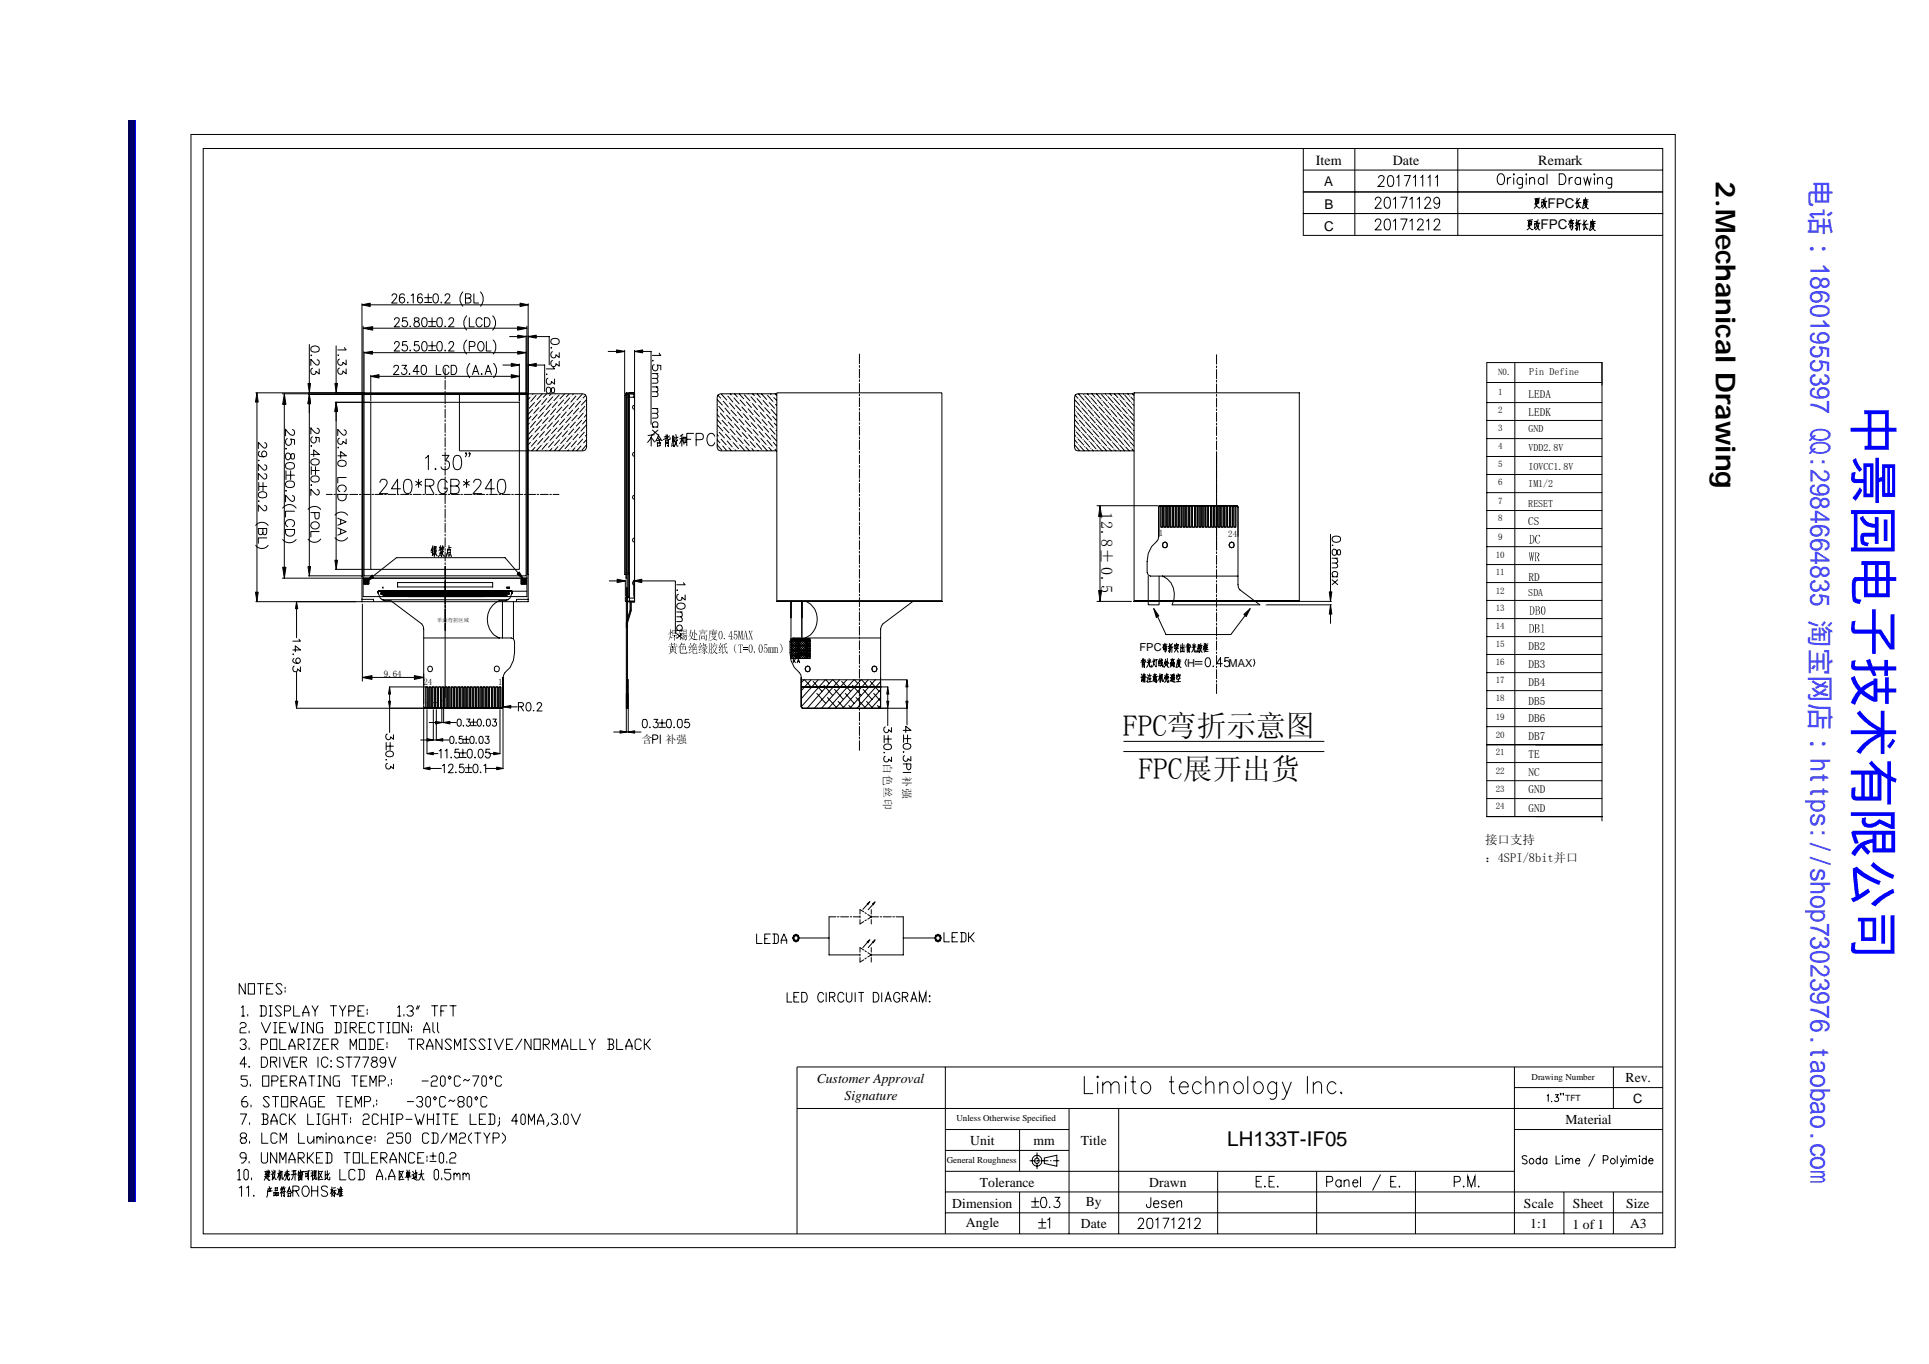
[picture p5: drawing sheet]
<svg xmlns="http://www.w3.org/2000/svg" width="297mm" height="210mm" viewBox="0 0 297 210" stroke-linecap="round" stroke-linejoin="round" font-family="sans-serif">
<defs><g id="words">
<text font-size="7.8" fill="#00f" x="285.7" y="62.3" transform="rotate(90 285.7 62.3)">中景园电子技术有限公司</text>
<g font-size="4.6">
<text x="172.9" y="113.3">FPC弯折示意图</text>
<text x="175.3" y="119.9">FPC展开出货</text>
</g>
<text font-size="4.2" x="264.2" y="27.9" transform="rotate(90 264.2 27.9)">2. Mechanical Drawing</text>
<text font-size="4.2" fill="#4040ff" x="278.8" y="27.7" transform="rotate(90 278.8 27.7)">电话：18601955397 QQ:2984664835 淘宝网店：https://shop73023976.taobao.com</text>
<text font-size="3.1" x="189" y="176.4">LH133T-IF05</text>
<text font-size="2.5" x="169.6" y="78.8" transform="rotate(90 169.6 78.8)">12.8±0.5</text>
<g font-size="2.2">
<text x="202.6" y="25.3">Item</text>
<text x="214.5" y="25.3">Date</text>
<text x="236.8" y="25.3">Remark</text>
</g>
<g font-size="2.1">
<text x="203.9" y="28.7">A</text>
<text x="203.9" y="35.6">C</text>
<text x="204" y="32.2">B</text>
<text x="237.2" y="35.3">FPC</text>
<text x="238.3" y="32">FPC</text>
<text x="125.8" y="166.6">Customer Approval</text>
<text x="250.3" y="166.6">Rev.</text>
<text x="130" y="169.4">Signature</text>
<text x="241.1" y="173.1">Material</text>
<text x="149.4" y="176.3">Unit</text>
<text x="159.1" y="176.3">mm</text>
<text x="166.4" y="176.3">Title</text>
<text x="146.6" y="185.9">Dimension</text>
<text x="150.9" y="182.7">Tolerance</text>
<text x="167.2" y="185.7">By</text>
<text x="177" y="182.7">Drawn</text>
<text x="234.7" y="185.9">Scale</text>
<text x="242.2" y="185.9">Sheet</text>
<text x="250.4" y="185.9">Size</text>
<text x="148.7" y="188.9">Angle</text>
<text x="166.4" y="189.1">Date</text>
<text x="235.6" y="189.1">1:1</text>
<text x="242.2" y="189.1">1 of 1</text>
<text x="251" y="189.1">A3</text>
</g>
<text font-size="2" x="251.5" y="169.8">C</text>
<g font-size="1.9">
<text x="228.7" y="130">接口支持</text>
<text x="228.7" y="132.7">：4SPI/8bit并口</text>
</g>
<g font-size="1.7">
<text x="235.4" y="64">LEDK</text>
<text x="235.4" y="61.2">LEDA</text>
<text x="235.3" y="80.8">CS</text>
<text x="235.4" y="89.4">RD</text>
<text x="175.5" y="100.3">FPC</text>
<text x="235.4" y="100.1">DB2</text>
<text x="182.8" y="102.6">H</text>
<text x="189.2" y="102.6">MAX</text>
<text x="235.4" y="102.8">DB3</text>
<text x="235.4" y="105.6">DB4</text>
<text x="235.4" y="108.6">DB5</text>
<text x="235.4" y="111.2">DB6</text>
<text x="235.4" y="113.9">DB7</text>
<text x="98.8" y="114.4">含</text>
<text x="102.5" y="114.4">补强</text>
<text x="136.1" y="117.4" transform="rotate(90 136.1 117.4)">白色丝印</text>
<text x="139.1" y="119.5" transform="rotate(90 139.1 119.5)">补强</text>
<text x="235.4" y="119.4">NC</text>
<text x="235.4" y="116.6">TE</text>
<text x="235.4" y="125">GND</text>
<text x="235.4" y="122.1">GND</text>
</g>
<g font-size="1.5">
<text x="235.5" y="57.8">Pin Define</text>
<text x="235.4" y="66.6">GND</text>
<text x="235.4" y="69.4">VDD2.8V</text>
<text x="235.3" y="74.9">IM1/2</text>
<text x="235.4" y="72.3">IOVCC1.8V</text>
<text x="235.3" y="78">RESET</text>
<text x="235.3" y="91.7">SDA</text>
</g>
<g font-size="1.4">
<text x="230.7" y="57.8">N0.</text>
<text x="230.7" y="60.9">1</text>
<text x="230.7" y="63.6">2</text>
<text x="230.7" y="66.4">3</text>
<text x="230.7" y="69.2">4</text>
<text x="230.7" y="71.9">5</text>
<text x="230.7" y="74.7">6</text>
<text x="230.7" y="77.5">7</text>
<text x="178.4" y="82.5">1</text>
<text x="189.1" y="82.6">24</text>
<text x="230.7" y="80.3">8</text>
<text x="230.7" y="83.1">9</text>
<text x="230.3" y="85.8">10</text>
<text x="230.3" y="88.6">11</text>
<text x="230.3" y="91.4">12</text>
<text x="230.3" y="94.1">13</text>
<text x="230.3" y="96.9">14</text>
<text x="230.3" y="99.7">15</text>
<text x="59.1" y="104.2">9.64</text>
<text x="65.2" y="105.4">24</text>
<text x="76.7" y="105.5">1</text>
<text x="230.3" y="102.4">16</text>
<text x="230.3" y="105.2">17</text>
<text x="230.3" y="108">18</text>
<text x="230.3" y="110.8">19</text>
<text x="230.3" y="113.5">20</text>
<text x="230.3" y="119.1">22</text>
<text x="230.3" y="116.3">21</text>
<text x="230.3" y="124.6">24</text>
<text x="230.3" y="121.9">23</text>
<text x="235.8" y="166.2">Drawing Number</text>
<text x="147.3" y="172.6">Unless Otherwise Specified</text>
<text x="145.8" y="179">General Roughness</text>
</g>
<text font-size="1.3" x="241" y="169.6">TFT</text>
<text font-size=".8" x="67.3" y="95.7">单面弯折区域</text>
</g></defs>
<path d="M20.9 18.6v166.5" fill="none" stroke="#00f" stroke-width=".25"/>
<path d="M19.9 18.6h.8v166.5h-.8z" fill="#00006b"/>
<path d="M19.8 18.6v166.5" fill="none" stroke="#005" stroke-width=".25"/>
<path d="M271 19.1h18.5v190.8h-18.5z" fill="#fff"/>
<g fill="none" stroke="#000" stroke-width=".15">
<path d="M29.4 20.7h228.6v171.4h-228.6zM31.3 22.9h224.7v167h-224.7zM200.7 26.2h55.3M200.7 29.5h55.3M200.7 22.9v13.3h55.3M200.7 32.9h55.3M208.6 22.9v13.3M211.8 30.8v-.3l.3-.1 .4 .1a.35 .35 0 0 1 .1 .5l-.9 1.1h1M211.8 34.1a.44 .44 0 0 1 .3-.4 .44 .44 0 0 1 .5 .3v.3l-.3 .5-.6 .6h1M212.3 27.4l.1-.2 .2-.2 .4 .1 .1 .3-.1 .4-.8 .9h1M213.4 30.5l.3-.1a.8 .8 0 0 1 .4 .9l-.2 .7-.3 .1a1.15 1.15 0 0 1-.2-1.6zM213.4 33.8l.3-.1a.79 .79 0 0 1 .4 1l-.2 .6-.3 .1a.77 .77 0 0 1-.5-1l.1-.4z"/>
<path d="M213.8 27.1l.4-.1a1.2 1.2 0 0 1 .2 1.6 .46 .46 0 0 1-.7-.2 1.67 1.67 0 0 1 .1-1.3zM214.6 30.7l.3-.3v1.7M214.6 34l.3-.3v1.7M215.1 27.3l.3-.3v1.7M215.7 30.4h1l-.7 1.7M215.7 33.7h1l-.7 1.7M216.2 27h1l-.7 1.7M217.1 30.7l.4-.3v1.7M217.1 34l.4-.3v1.7M217.6 27.3l.4-.3v1.7M218.2 30.7l.4-.3v1.7M218.3 34.1l.3-.4h.3l.2 .2a.65 .65 0 0 1-.1 .7l-.8 .8h1"/>
<path d="M218.7 27.3l.4-.3v1.7M219.4 30.8l.3-.4h.3l.3 .3-.2 .5-.7 .9h1M219.7 34l.3-.3v1.7M219.9 27.3l.3-.3v1.7M220.8 34.1l.3-.4h.3l.2 .2a.65 .65 0 0 1-.1 .7l-.7 .8h1M221 27.3l.3-.3v1.7M221.7 30.9a.5 .5 0 0 1-.5 .5 .51 .51 0 0 1-.4-.7 .51 .51 0 0 1 .8-.1 1.84 1.84 0 0 1-.1 1.4l-.4 .1-.3-.3M224.5 22.9v13.3M230.8 26.8a.57 .57 0 0 1 .6 0 .57 .57 0 0 1 .3 .6 .7 .7 0 0 1-.7 1 1.05 1.05 0 0 1-.2-1.6zM232.1 27.3v1.1M232.7 27.3a.49 .49 0 0 0-.6 .5M233.1 26.8h.1l-.1 .1z"/>
<path d="M233.1 27.3v1.1M234.4 27.3v1.6l-.2 .1-.4-.1M234.4 27.6a.45 .45 0 0 0-.5-.3 .45 .45 0 0 0-.3 .5v.3l.2 .2 .4 .1 .2-.2M235 26.8v.1zM235 27.3v1.1M235.3 34.8l.6 .6 .2-.1M235.4 34.1v.6M235.5 27.6l.4-.3 .3 .1 .1 .2v.8M235.5 27.3v1.1M235.6 33.9l-.1 1.1-.4 .4M235.8 34.4h-.4M235.9 34.1h-.5"/>
<path d="M235.9 34.6l-.5 .1M235.9 34l-.1 .6M236 33.8l-.8 .1M236.3 31.4l.7 .6h.2M236.3 34.4v.8l.3-.3M236.4 30.7v.7M236.6 34.1h-.3M236.6 34v.4M236.6 34.4l-.3 .1M236.7 30.5a1.31 1.31 0 0 1-.5 1.6M236.7 34.6l.3 .8h.2M236.8 33.8l-.2 1"/>
<path d="M236.9 31l-.4 .1M237 34.4a1.26 1.26 0 0 1-.6 1M237 30.8h-.6M237 31.2l-.6 .1M237 30.7l-.1 .5M237.1 30.5l-.8 .1M237.1 34.3l-.4 .1M237.4 31.1v.7M237.7 30.7l-.3 .1M237.7 30.7l-.1 .4M237.7 31.1h-.3M237.7 31.5l-.3 .4"/>
<path d="M237.7 27.6a.52 .52 0 0 0-.9 .1 .52 .52 0 0 0 .6 .7l.3-.2M237.7 27.3v1.1M237.8 31.2l.3 .8h.1M237.9 30.4l-.2 1M238.1 31a1.37 1.37 0 0 1-.6 1.1M238.2 31h-.4M238.2 26.8v1.6M240.1 26.8a.89 .89 0 0 1 1 .5 .89 .89 0 0 1-.3 1l-.7 .1zM241.6 27.3v1.1M241.8 34.1l-.3 .5M241.8 34.6v.4M241.9 34v.4"/>
<path d="M241.9 33.7l.1 .2M242 34v.4M242.1 34.1l.2 .3M242.2 35.1l-.2 .3-.1-.2M242.2 34.4l-.4 .1M242.2 27.3a.46 .46 0 0 0-.6 .5M242.2 34.4v.3l-.4 .1M242.2 34.9l-.4 .1M242.2 34.8v.4M242.3 33.9l-.7 .1M242.8 33.8v1.6l-.2-.3M242.8 30.5v1.5"/>
<path d="M242.9 34.5l-.3 .3M242.9 34.3l-.3 .1M243 31.2l.3 .7h.1M243 33.9l-.1 1.5M243.1 31.7l-.3 .3M243.2 30.5l-.4 .6M243.2 34.5v1M243.3 33.9l-.3 .2M243.4 27.6a.52 .52 0 0 0-.9 .1 .52 .52 0 0 0 .6 .7l.3-.2M243.4 27.3v1.1M243.4 31.2l-.9 .1M243.4 34.4l-.4 .1"/>
<path d="M243.9 27.3l.3 1.1 .2-1.1 .3 1.1 .3-1.1M243.9 30.7l-.3 1.4M243.9 33.9v1.4M244 31.6l.5 .5h.1M244 34.6l.4 .7 .1-.1M244.1 30.8v.6M244.1 30.4l.1 .3M244.1 35l-.2 .4M244.3 33.9l-.4 .5M244.3 30.8v.5M244.4 31.3h-.3M244.4 31.5h-.4"/>
<path d="M244.4 31.4l-.2 .5-.4 .2M244.5 30.8h-.6M244.5 31.1h-.6M244.5 34.5l-.9 .1M245 34l-.1 1.2-.2 .3M245.1 35l.6 .5M245.2 34.2v.6M245.2 33.8l.1 .3M245.4 26.8h.2l-.1 .1zM245.4 34.6l-.2 .1M245.4 34.1v.5M245.5 34.8l-.2 .4-.4 .3"/>
<path d="M245.5 34.8l-.4 .1M245.5 27.3v1.1M245.6 34.1l-.6 .1M245.6 34.4l-.6 .1M246 27.6l.4-.3 .3 .1 .1 1M246 27.3v1.1M248.2 27.3l-.1 1.6-.2 .1-.3-.1M248.2 27.6a.45 .45 0 0 0-.5-.3 .45 .45 0 0 0-.4 .5l.2 .5 .5 .1 .2-.2M47.4 59h.4l-.2 1.5zM47.6 53v6M47.9 53.5a.65 .65 0 0 1 .9-.3 .65 .65 0 0 1 .3 .8l-.2 .1a.62 .62 0 0 1-.7 .1 .62 .62 0 0 1-.3-.7zM48 54.7l-.1-.1v.2"/>
<path d="M48.1 56.7a.48 .48 0 0 0-.2 .7 .48 .48 0 0 0 .7 .1v-.4l.6 .5v-.8M48.8 55.4l.3 .1 .1 .4-.2 .2-.2 .1-.9-.9v1M51.6 59h.4l-.2 1.5zM51.8 53.2v5.8M52.1 54.7v-.1v.1M52.3 55.3a.47 .47 0 0 0-.3 .7 .47 .47 0 0 0 .7 .1l.1-.3 .5 .4v-.8M52.3 56.7a.49 .49 0 0 0-.3 .6 .49 .49 0 0 0 .7 .3l.1-.5 .5 .5v-.8M53.1 53.5l.2 .4h-1.3M55.7 46.8v13.5M55.7 46.9l1.3-.2v.5zM55.9 50.2v10.1M55.9 50.5l1.5-.2v.5z"/>
<path d="M56.1 54.3l1.2-.2v.4zM56.1 54.1v6.5M57 46.9h23.1M57.1 57.8v3.9M57.1 57.9l1.3-.2v.5zM57.3 54.3h22.4M57.4 50.5h22.3M58.4 57.9h20.3M60.4 45.6a.36 .36 0 0 1 .4-.4 .36 .36 0 0 1 .3 .4l-.8 1.1h.9M60.6 56.6a.36 .36 0 0 1 .4-.4 .36 .36 0 0 1 .4 .4l-.8 1.1h.8M60.8 52.9l.1-.2 .3-.1 .2 .1 .1 .3-.8 1h.8M60.8 49.2v-.2l.2-.1 .4 .1a1.02 1.02 0 0 1-.6 1.2l-.1 .1h.8"/>
<path d="M61.9 56.2h.7l-.4 .6a.44 .44 0 0 1 .4 .7 .44 .44 0 0 1-.8-.1M62.3 45.4a.38 .38 0 0 0-.4-.2 .38 .38 0 0 0-.3 .3 .88 .88 0 0 0 .3 1.2 .42 .42 0 0 0 .4-.4 .42 .42 0 0 0-.3-.5 .42 .42 0 0 0-.5 .4M62.6 52.6h-.6v.6a.46 .46 0 0 1 .7 0 .46 .46 0 0 1-.1 .7 .46 .46 0 0 1-.7-.1M62.6 48.9h-.6v.6l.2-.1h.3l.2 .2 .1 .3a.45 .45 0 0 1-.4 .4 .45 .45 0 0 1-.5-.3M62.8 46.5v.2l.1-.1M63.1 57.5v.2v-.1M63.2 53.9l-.1 .1h.1M63.2 50.2h-.1h.1M63.3 45.5l.3-.3v1.5M63.8 49v.2a.54 .54 0 0 0 .6 .4l.2 .2v.3l-.2 .2h-.4a.46 .46 0 0 1-.2-.6 .46 .46 0 0 1 .5-.3 .29 .29 0 0 0 .2-.4zM64.5 52.6h-.6l-.1 .6a.45 .45 0 0 1 .7 0 .45 .45 0 0 1-.1 .7 .45 .45 0 0 1-.7-.1M64.5 57.2h-.9l.6-1v1.5"/>
<path d="M65 56.3a.43 .43 0 0 1 .6 .2 .76 .76 0 0 1-.4 1.2 1.02 1.02 0 0 1-.2-1.4zM65 45.4l-.1-.1a.41 .41 0 0 0-.5 .2 .88 .88 0 0 0 .3 1.2 .41 .41 0 0 0 .4-.4 .41 .41 0 0 0-.4-.5 .41 .41 0 0 0-.4 .4M65.1 52.7l.3-.1a.95 .95 0 0 1 0 1.4h-.1a.8 .8 0 0 1-.3-1.1zM65.1 49a.39 .39 0 0 1 .6 .1 1.02 1.02 0 0 1-.3 1.2h-.1a.92 .92 0 0 1-.2-1.3zM65.4 45.8h1.1M65.4 46.6h1.1M65.9 45.2v1.2M66 53.2h1.1M66 54h1.1M66 49.5h1.1M66 50.2h1.1M66.5 48.9v1.2"/>
<path d="M66.5 52.6v1.2M66.9 45.3a.4 .4 0 0 1 .5 .2 .77 .77 0 0 1-.4 1.2 .97 .97 0 0 1-.1-1.4zM67.2 56.2v1.5h.7M67.4 52.7l.4-.1a.86 .86 0 0 1 .3 1.2 .4 .4 0 0 1-.7 .2 1.21 1.21 0 0 1 0-1.3zM67.4 49a.42 .42 0 0 1 .7 .1v.4a.59 .59 0 0 1-.5 .8 .92 .92 0 0 1-.2-1.3zM68 46.5v.2v-.1M68.5 45.6a.36 .36 0 0 1 .4-.4 .36 .36 0 0 1 .4 .4l-.8 1.1h.8M68.5 53.9v.1h.1M68.5 50.2h.1M68.5 56.7v1.1M68.5 58v.3M68.5 58.6v1.3"/>
<path d="M69.1 56.6a.47 .47 0 0 0-.5-.4 .47 .47 0 0 0-.4 .6 .71 .71 0 0 0 .6 .9l.3-.4M69.1 52.9l.1-.2a.4 .4 0 0 1 .6 0 .4 .4 0 0 1-.1 .6l-.6 .7h.8M69.1 49.2l.3-.3h.2l.3 .2-.2 .6-.6 .6h.8M69.5 56.2h.4a.79 .79 0 0 1 .4 .7 .79 .79 0 0 1-.4 .8h-.4zM71.3 44.9a1.56 1.56 0 0 0 0 2.2M71.7 45.9a.57 .57 0 0 0 .8-.4l-.3-.3h-.5v1.5h.5a.39 .39 0 0 0 .3-.4 .39 .39 0 0 0-.3-.4M71.9 52.3a1.51 1.51 0 0 0 0 2.2M71.9 48.6a1.56 1.56 0 0 0 0 2.2M72.3 53.3h.6l.2-.1v-.3l-.1-.2-.7-.1v1.4M72.3 48.9v1.4h.7M72.3 55.9a1.62 1.62 0 0 0 0 2.2M72.8 57.7l.4-1.5 .5 1.5"/>
<path d="M72.9 57.2h.6M73 45.2v1.5h.7M73.7 52.8l.2-.2a.78 .78 0 0 1 .7 .6 .78 .78 0 0 1-.3 .8 .64 .64 0 0 1-.7-.3 .64 .64 0 0 1 0-.7zM74 44.9a1.62 1.62 0 0 1 0 2.2M74.2 57.5v.2v-.1M74.2 49.2a.48 .48 0 0 0-.5-.3 .48 .48 0 0 0-.4 .5v.4a.52 .52 0 0 0 .8 .4l.1-.2M74.6 48.9h.4a.72 .72 0 0 1 .4 .9 .72 .72 0 0 1-.8 .5zM74.7 57.7l.5-1.5 .5 1.5M74.9 52.6v1.4h.7M74.9 57.2h.6M75.9 48.6a1.56 1.56 0 0 1 0 2.2M75.9 52.3a1.57 1.57 0 0 1 0 2.2"/>
<path d="M76 55.9a1.56 1.56 0 0 1 0 2.2M77.4 56.2h1.3M78.5 51.8h1.2M78.7 57.7l1.3 .2-1.3 .3zM78.7 55.9l1.3 .3-1.3 .2zM79.7 50.3l1.4 .2-1.4 .3zM79.7 54.1l1.3 .2-1.3 .2zM79.7 51.6l1.3 .2-1.3 .2zM80 56v5.7M80.1 46.7l1.2 .2-1.2 .3zM81 51.7v8.9M81.1 50.2v10.1"/>
<path d="M81.3 46.8v13.5M81.3 56.2l1.3-.3v.5zM81.3 51.8l1.3-.2v.4zM82.6 56.2h1.3v4.1M82.6 51.8h2v4.4M84.2 59.7h.1a.34 .34 0 0 1 .5 .1l.2 .6 .2 .1a.44 .44 0 0 0 .2-.5 .44 .44 0 0 0-.3-.3h-.1l-.2 .6-.3 .3-.2-.1-.2-.2zM84.3 57.6h-.1v.1M84.4 58.3a.49 .49 0 0 0-.2 .6 .49 .49 0 0 0 .6 .2l.1-.4 .5 .4v-.7M84.9 52.3a.77 .77 0 0 1 1.2 .2v.2a.73 .73 0 0 1-1.3 0zM84.9 53.6v-.1v.1M85.1 54.1a.46 .46 0 0 0-.2 .8 .46 .46 0 0 0 .7-.1v-.2l.5 .4v-.7M85.1 55.5a.46 .46 0 0 0-.2 .7 .46 .46 0 0 0 .7 0v-.2l.5 .4v-.8"/>
<path d="M85.1 56.5l.3 .3h-1.3M93.6 54.1h1.3M94.9 53.9l1.3 .2-1.3 .2zM96.2 53.9v6.8M97.7 53.9v6.4M97.7 54.1l1.3-.2v.4zM99 54.1h1.3v11.2M100.5 57.5h.8M100.5 59.6h.8M100.6 55.5h-.1v.1M100.7 56.1a.49 .49 0 0 0-.2 .8 .49 .49 0 0 0 .7 .1 .49 .49 0 0 0 0-.8l.6 .1v.6M101.1 57.5a.5 .5 0 0 1 .1 .7l-.7 .1"/>
<path d="M101.1 58.3a.52 .52 0 0 1 .1 .6l-.7 .1M101.1 59.6a.43 .43 0 0 1 0 .7h-.6M101.5 54.4l.3 .3h-1.3M132.3 54.5v1.5M132.3 56.3v.3M132.3 56.8v1.4M132.3 58.5v.2M132.3 59v1.4M187.3 54.6v1.4M187.3 56.3v.3M187.3 56.9v1.4M187.3 58.5v.3"/>
<path d="M187.3 59.1v1.4M228.9 58.9h17.8M233.3 55.8v69.9M39.4 60.5h41.9v32.1h-25.6M39.6 60.5h.1M39.6 61.9v29.3M39.6 60.5l.2 1.4h-.5zM39.8 75.9a.65 .65 0 0 1 .9-.2 .65 .65 0 0 1 .3 .8l-.5 .1a.59 .59 0 0 1-.7-.3zM39.8 74.3v1.2M39.9 70.9l-.1-.1v.2M39.9 77.2l-.1-.1v.1M40 69.5a.43 .43 0 0 0 0 .8 1.02 1.02 0 0 0 1-.2l.1-.3a.39 .39 0 0 0-.6-.3 .45 .45 0 0 0-.2 .5 .45 .45 0 0 0 .3 .3"/>
<path d="M40 74.9h1.1M40.5 74.3v1.2M40.8 68.2a.42 .42 0 0 1 .3 .4 .42 .42 0 0 1-.4 .4l-.9-.9v.9M40.8 71.6l.3 .2v.3l-.3 .3-.2-.1-.8-.8v.9M40.8 72.9l.1 .1 .2 .2-.1 .4-.2 .1h-.2l-.8-.8v.9M40.8 77.8l.3 .3v.3l-.3 .2h-.2l-.8-.9v1M43.5 60.6h12.1M43.5 78.2a1.27 1.27 0 0 1 2.1 0M43.8 62.3v25M43.8 60.6l.2 1.7h-.5zM44 71.4a.84 .84 0 0 1 1.3 .2v.2a.77 .77 0 0 1-.6 .4 .77 .77 0 0 1-.7-.4zM44 74.3a.84 .84 0 0 1 1.3 .2v.3a1.01 1.01 0 0 1-1.3 0z"/>
<path d="M44 72.5v1.3M44.1 69.8l.3-.1a1.15 1.15 0 0 1 .5 .9l.3 .1a.53 .53 0 0 0 0-.9l-.3 .1-.1 .4a.4 .4 0 0 1-.4 .5 .4 .4 0 0 1-.4-.4zM44.1 69.1l-.1-.1v.2M44.1 75.6l-.1-.1v.1M44.2 73.2h1.1M44.2 67.5a.53 .53 0 0 0-.2 .7 .53 .53 0 0 0 .7 .3l.2-.3-.1-.6 .5 .1v.7M44.8 72.5v1.3M45 66.1a.49 .49 0 0 1 .2 .9h-.3l-.4-.3-.5-.6v1M45 76.3l.2 .1a.54 .54 0 0 1 .1 .6l-.2 .2-.3-.1-.8-.9v1.1M45.3 78.7h-1.3v.9M47.4 78.4a1.24 1.24 0 0 1 2 0M47.5 60.7h8.4"/>
<path d="M47.6 60.5h.1M47.6 62.1v25.1M47.6 60.7l.2 1.4h-.4zM47.9 70h1.3l-.9-.7v1M47.9 78.9h1.3v.6l-.3 .4-.3-.1-.1-.9M47.9 70.8a.78 .78 0 0 1 1.3 .2v.2a.7 .7 0 0 1-.7 .4 .7 .7 0 0 1-.6-.4zM47.9 73.5a.77 .77 0 0 1 1.3 .2v.1a.68 .68 0 0 1-.7 .4 .68 .68 0 0 1-.6-.5zM47.9 71.8v1.2M48 68.7l-.1-.1v.1M48 74.7l-.1-.1v.1M48.1 72.4h1.1M48.1 67.2a.48 .48 0 0 0-.2 .7 .48 .48 0 0 0 .6 .2l.2-.5-.1-.3 .6 .1v.7"/>
<path d="M48.6 71.8v1.2M48.8 65.9l.3 .1v.5l-.1 .2h-.2l-.4-.2-.5-.7v1M48.8 75.4l.4 .2-.1 .5a.27 .27 0 0 1-.5 0l-.7-.8v1M50.3 76.1h.9M51.4 76.1h.3M51.6 79.3a1.21 1.21 0 0 1 1.9 0M51.6 61.9h5.3M51.8 60.5h.1M51.8 63.4v22.9M51.8 61.9l.2 1.5h-.4zM51.9 76.1h1.2M52 76.1h1.3a.69 .69 0 0 1-.4 1 .69 .69 0 0 1-.9-.5z"/>
<path d="M52 70.2h1.3l-.8-.7v1M52 79.8l1.3 .5-1.3 .6M52.1 71.1a.65 .65 0 0 1 .8-.3 .65 .65 0 0 1 .3 .8l-.1 .1a.62 .62 0 0 1-.8 .1 .62 .62 0 0 1-.2-.7zM52.1 68.9h-.1l.1 .1M52.3 67.5a.47 .47 0 0 0-.3 .6 .47 .47 0 0 0 .7 .2l.1-.4 .5 .4v-.7M52.3 75.7a.56 .56 0 0 1-.2-.7 .56 .56 0 0 1 .7-.3l.5 .3-.1 .5-.2 .2M52.5 80v.6M53 66.2l.3 .2v.3l-.2 .3-.5-.2-.6-.7v1M53.3 73.5h-1.3v.9M53.4 76.1h.2M53.9 76.1h1.2M55.3 76.1h.3"/>
<path d="M55.7 60.5v32.1M55.8 76.1h1.2M56.1 60.7h24.9v27.9h-24.9zM56.1 60.7v.1M57.1 61.9h22.9v25.8h-22.9zM57.1 61.9v.1M57.3 76.1h.2M57.7 76.1h1.3M58.5 74.3l.2-.4 .5-.1a.53 .53 0 0 1 .3 .8l-1.1 1.4h1.3M59.2 76.1h.3M59.7 76.1h1.2M61.2 76.1h.2"/>
<path d="M61.7 75.2h-1.4l.9-1.4v2.2M61.7 76.1h1.2M62.4 73.9a.64 .64 0 0 1 1 .3 2.16 2.16 0 0 1-.2 1.7 .62 .62 0 0 1-1-.3 2.03 2.03 0 0 1 .2-1.7zM63.1 76.1h.3M63.6 76.1h1.3M64 74.1l.9 .6M64.5 73.8v1.2M64.9 74.1l-.9 .6M65.1 76.1h.3M65.5 70.5l.5-.4v2.2M65.5 74.8a1.34 1.34 0 0 0 1.3-.3v-.3l-.2-.3-.3-.1h-.8v2.2M65.6 76.1h1.2"/>
<path d="M66.2 74.8l.6 1.2M67.1 72.1l-.1 .1 .1 .1v-.1M67.1 76.1h.2M67.6 76.1h1.2M68.1 70.1h1l-.5 .9a.69 .69 0 0 1 .6 .7 .69 .69 0 0 1-.8 .6l-.3-.1-.2-.3M68.5 60.2v.3M68.5 60.8v1.3M68.5 62.4v.3M68.5 63v1.3M68.5 64.6v.3M68.5 65.2v1.4M68.5 66.8v.3"/>
<path d="M68.5 67.4v1.4M68.5 69v.3M68.5 69.6v1.4M68.5 71.2v.3M68.5 71.8v1.4M68.5 73.4v.3M68.5 74v1.4M68.5 75.6v.3M68.5 76.2v1.3M68.5 77.8v.3M68.5 78.4v1.4M68.9 74.3a.7 .7 0 0 0-.8-.5 .7 .7 0 0 0-.6 .6 1.3 1.3 0 0 0 .5 1.6 .71 .71 0 0 0 .9-.9h-.5"/>
<path d="M69 76.1h.3M69.4 74.8a1.29 1.29 0 0 0 1.3-.3v-.3l-.2-.3-.3-.1h-.8v2.2h.8a.6 .6 0 0 0 .5-.6 .6 .6 0 0 0-.5-.6M69.5 76.1h1.2M70 70.2a.62 .62 0 0 1 1 .3 2.06 2.06 0 0 1-.2 1.7 .62 .62 0 0 1-.9-.3 2.08 2.08 0 0 1 .1-1.7zM70.7 60.6v8.8h19.1l.4-.1 .1-.4v-7.7l-.1-.4-.4-.2h-33.9v31.2h25.2v-31.2M71 76.1h.2M71.4 74.1l.9 .6M71.5 76.1h1.2M71.8 69.8l-.1 .1v-.1v-.1a.42 .42 0 0 1 0 .6M71.8 73.8v1.2M72.3 74.1l-.9 .6M72.4 69.8l-.1 .1v-.2a.44 .44 0 0 1-.1 .6"/>
<path d="M72.9 74.3l.2-.4 .6-.1a.53 .53 0 0 1 .3 .8l-1.2 1.4h1.4M72.9 76.1h.3M73.4 76.1h1.2M74.9 76.1h.2M75.4 76.1h1.2M76.1 75.2h-1.4l.9-1.4v2.2M76.8 76.1h.3M76.9 73.9a.59 .59 0 0 1 .9 .3 2.14 2.14 0 0 1-.2 1.7 .62 .62 0 0 1-.9-.3 2.03 2.03 0 0 1 .2-1.7zM77.3 76.1h1.3M78.8 76.1h.2M79.3 76.1h1.2M80 61.9v.1"/>
<path d="M80.8 76.1h.2M81 60.7v.1M81.2 67.1h.1M81.2 76.1h1.3M81.3 63.1h.1M81.3 66.2l-.1 .1M81.4 62.2l-.2 .2M81.4 60.6l-.2 .3M81.5 66h.1M81.5 69.1l-.3 .3M81.5 62h.1M81.5 65.1l-.3 .4"/>
<path d="M81.6 61.2l-.4 .4M81.6 68.9h.1M81.7 64.9v.1M81.7 68.1l-.5 .6M81.8 60.9v.1M81.8 64.1l-.6 .7M81.9 67.8v.1M82 63.9h.1M82 67l-.8 .9M82 63l-.8 .9M82.1 60.6l-.1 .2M82.2 66.8h.1"/>
<path d="M82.2 62.8h.1M82.2 65.9l-.8 1M82.3 61.9l-.8 1M82.4 65.7h.1M82.4 68.8l-.5 .6M82.5 61.7h.1M82.5 64.8l-.9 1M82.6 60.8l-.9 1M82.6 68.6v.1M82.7 64.7h.1M82.7 67.7l-.9 1M82.7 76.1h.3"/>
<path d="M82.7 60.7h.1M82.7 63.8l-.8 .9M82.8 67.6h.1M82.9 63.6h.1M82.9 66.7l-.9 1M83 62.7l-.8 1M83.1 66.5h.1M83.2 62.5h.1M83.2 65.6l-.9 1M83.2 76.1h1.2M83.3 61.6l-.9 1M83.3 69.4h.1"/>
<path d="M83.4 65.4v.1M83.4 68.5l-.8 .9M83.4 61.4v.1M83.4 64.6l-.8 .9M83.5 60.6l-.8 .9M83.5 68.3v.1M83.6 64.3v.1M83.6 67.5l-.9 1M83.7 63.5l-.9 1M83.8 67.3h.1M83.9 63.3h.1M83.9 66.4l-.9 1"/>
<path d="M84 62.4l-.9 1M84.1 66.2h.1M84.1 69.3l-.1 .1M84.1 62.2v.1M84.1 65.3l-.8 1M84.2 60.6l-.6 .6M84.2 61.3l-.8 1M84.2 69.1v.1M84.3 65.1v.1M84.3 68.2l-.9 1M84.4 61.2h.1M84.4 64.3l-.9 .9"/>
<path d="M84.5 68.1h.1M84.6 64.1h.1M84.6 67.2l-.9 .9M84.7 63.2l-.9 1M84.7 76.1h.2M84.8 67h.1M84.8 63h.1M84.8 66.1l-.8 1M84.9 60.6l-.3 .3M84.9 62.1l-.8 1M85 65.9h.1M85 69l-.3 .4"/>
<path d="M85.1 61.9v.1M85.1 65l-.9 1M85.2 61l-.9 1M85.2 68.8v.1M85.2 76.1h.9M85.3 64.8v.1M85.3 67.9l-.9 1M85.4 60.8v.1M85.4 63.9l-.9 1M85.5 67.7v.1M85.5 63.8h.1M85.5 66.9l-.8 .9"/>
<path d="M85.6 60.6l-.1 .1M85.6 62.9l-.8 1M85.7 66.7h.1M85.8 62.7h.1M85.8 65.8l-.9 1M85.9 61.8l-.9 1M85.9 65.6h.1M85.9 68.7l-.5 .7M86 61.6h.1M86 64.7l-.8 1M86.1 60.8l-.8 .9M86.1 68.5v.1"/>
<path d="M86.2 64.6h.1M86.2 67.7l-.8 .9M86.3 63.7l-.8 1M86.4 67.5h.1M86.5 63.5h.1M86.5 66.6l-.9 1M86.6 62.6l-.9 1M86.6 66.4h.1M86.7 62.4h.1M86.7 65.5l-.8 1M86.8 61.5l-.9 1M86.8 69.3h.1"/>
<path d="M86.9 65.3v.1M86.9 68.5l-.9 .9M87 60.6l-.8 .8M87 61.3v.1M87 64.5l-.9 .9M87.1 68.2v.1M87.2 64.3h.1M87.2 67.4l-.9 .9M87.2 63.4l-.8 .9M87.3 67.2h.1M87.4 63.2h.1M87.4 66.3l-.8 1"/>
<path d="M87.5 62.3l-.9 1M87.6 66.1h.1M87.6 69.2l-.2 .2M87.7 60.6l-.5 .6M87.7 62.1h.1M87.7 65.2l-.9 1M87.8 61.2l-.9 1M87.8 69h.1M87.9 65v.1M87.9 68.1l-.9 1M87.9 61v.1M87.9 64.2l-.8 .9"/>
<path d="M88 67.9v.1M88.1 63.9v.1M88.1 67.1l-.9 1M88.2 63.1l-.9 1M88.3 66.9h.1M88.3 60.6l-.2 .2M88.4 62.9h.1M88.4 66l-.9 1M88.5 62l-.9 1M88.6 65.8h.1M88.6 68.9l-.5 .5M88.6 61.8v.1"/>
<path d="M88.6 64.9l-.8 1M88.7 60.9l-.8 1M88.7 68.7v.1M88.8 64.7v.1M88.8 67.8l-.9 1M88.9 60.8h.1M88.9 63.9l-.9 .9M89 67.7h.1M89.1 63.7h.1M89.1 66.8l-.9 .9M89.2 62.8l-.9 1M89.2 66.6h.1"/>
<path d="M89.3 62.6h.1M89.3 65.7l-.8 1M89.4 61.7l-.8 1M89.5 65.5h.1M89.5 68.6l-.7 .8M89.6 61.5v.1M89.6 64.7l-.9 .9M89.7 60.7l-.9 .9M89.7 68.5h.1M89.8 64.5h.1M89.8 67.6l-.9 .9M89.8 63.6l-.8 1"/>
<path d="M89.9 67.4h.1M90 63.4h.1M90 66.5l-.8 1M90.1 62.5l-.9 1M90.2 66.3h.1M90.2 60.8l-.4 .5M90.3 62.3v.1M90.3 65.4l-.9 1M90.3 61.5l-.8 .9M90.3 63l-.1 .2M90.3 63.8l-.4 .5M90.3 64.6l-.6 .7"/>
<path d="M90.3 66.9l-.2 .3M90.3 67.7l-.5 .5M90.3 68.5l-.7 .8M96.4 60.8h-.2v27.6h.2M96.5 60.6v31.2h.2v-31.2M96.7 60.8h.2M96.9 60.5v31.5h-.6v.6h1.4M97 60.5h.7M97.6 61.2v-.6h-1.2v28.4h.1M97.7 76.2l-.2 .1-.1 .2 .1 .3 .2 .1M97.7 69.6l-.2 .1-.1 .3 .1 .2 .2 .1M97.7 62.4l-.2 .1-.1 .2 .1 .2 .2 .1"/>
<path d="M97.7 60.5h-1.3v.1M97.7 60.5v32.1h-1.3v-.1h1.3M97.7 61.2h-1.3v27h.5v4.3M100.3 67.4v1.3M100.4 67l-.2 .5-.5 .6M100.4 67.5l.4 .6M100.5 62.9h.8M100.5 65.7h.8M100.5 66.2l.8 .8M100.7 65.7a.44 .44 0 0 1-.1-.6 .44 .44 0 0 1 .6 0 .44 .44 0 0 1 0 .6M100.8 66.9l-1 .1M101.1 60.3a.43 .43 0 0 1 0 .7h-.6"/>
<path d="M101.1 62.9a.5 .5 0 0 1 .1 .7h-.7M101.1 63.6a.52 .52 0 0 1 .1 .7l-.7 .1M101.2 68.1v.6M101.3 66.2l-.8 .8M101.4 67.4l.1 .3M101.4 67.1l.5 .7h.1M101.4 66.9l-.4 1M101.6 67.7l-.1 .5M101.6 67.7l-.4 .1M101.7 68.6l-.5 .1M101.7 68.2h-.5M101.7 68.1l-.1 .5"/>
<path d="M102.5 67.8v1M102.6 66.9v.8M102.6 67.5l-.4 .2M102.6 67.2l-.3 .1M102.8 66.9v.8l.4-.1v-.2M102.8 68.1h-.3M102.8 68.3h-.3M102.9 67.8v.9l-.1-.1M102.9 67.8l-.4 .1M103.1 67.1l-.3 .3M103.6 67.1v.8M103.6 67.9l-.2 .8"/>
<path d="M103.6 68.6l.1 .1M103.7 67.9h-.1M103.7 67.6h-.1M103.7 67.1v1.6M103.7 67.2h-.1M104 67.9l.3 .8h.1M104 67.6l-.2 .3M104.1 66.9v.3M104.2 67.8l-.4 1M104.2 67.5l.1 .3M104.4 67.3l-.6 .1M105 67.7l.2 .2"/>
<path d="M105 67.6l-.3 .7M105 67v1.7M105.2 66.8l-.5 .4M105.2 67.4l-.5 .2M105.3 67.2v1.2M105.6 67.4h-.3M105.6 67.3v.8M105.6 68.1l-.3 .1M105.8 67.6h.6M106.8 66.7h-1v1.9M107.2 67.7a1 1 0 0 0 1.1-.3v-.3l-.2-.3-.2-.1h-.7v1.9M110.1 67.2a.59 .59 0 0 0-.8-.5 1.18 1.18 0 0 0 0 1.9 .58 .58 0 0 0 .8-.4"/>
<path d="M110.4 68.5l.8 .8M110.4 67.7l.5 .5M110.4 66.9l.2 .3M110.4 64.6l.7 .7M110.4 63.8l.4 .5M110.4 63l.2 .2M110.4 61.5l.9 .9M110.5 65.4l.8 1M110.5 62.3v.1M110.5 60.8l.5 .5M110.6 66.3h.1M110.6 62.5l.9 1"/>
<path d="M110.7 66.5l.9 1M110.7 63.4h.1M110.8 67.4h.1M110.9 63.6l.8 1M111 67.6l.9 .9M111 64.5h.1M111.1 68.5h.1M111.1 60.7l.8 .9M111.2 64.7l.8 .9M111.2 61.5v.1M111.3 68.6l.6 .8M111.3 65.5h.1"/>
<path d="M111.3 61.7l.9 1M111.4 65.7l.9 1M111.4 62.6h.1M111.5 66.6h.1M111.6 62.8l.8 1M111.7 66.8l.8 .9M111.7 63.7h.1M111.7 67.7h.1M111.9 63.9l.8 .9M111.9 60.8h.1M111.9 67.8l.9 1M111.9 64.7v.1"/>
<path d="M112 68.7v.1M112 60.9l.9 1M112.1 64.9l.9 1M112.1 61.8v.1M112.2 68.9l.4 .5M112.2 65.8h.1M112.3 62l.9 1M112.4 66l.8 1M112.4 62.9h.1M112.4 60.6l.2 .2M112.4 66.9h.1M112.5 63.1l.9 1"/>
<path d="M112.6 67.1l.9 1M112.6 63.9v.1M112.7 67.9v.1M112.8 64.2l.9 .9M112.8 61v.1M112.9 68.1l.9 1M112.9 65v.1M113 69h.1M113 61.2l.9 1M113.1 65.2l.8 1M113.1 62.1h.1M113.1 60.6l.5 .6"/>
<path d="M113.2 69.2l.1 .2M113.2 66.1h.1M113.2 62.3l.9 1M113.3 66.3l.9 1M113.3 63.2h.1M113.4 67.2h.1M113.5 63.4l.9 .9M113.6 67.4l.9 .9M113.6 64.3h.1M113.7 68.2v.1M113.8 64.5l.8 .9M113.8 61.3v.1"/>
<path d="M113.8 60.6l.8 .8M113.9 68.5l.8 .9M113.9 65.3v.1M113.9 69.3h.1M113.9 61.5l.9 1M114 65.5l.9 1M114 62.4h.1M114.1 66.4h.1M114.2 62.6l.8 1M114.3 66.6l.9 1M114.3 63.5h.1M114.4 67.5h.1"/>
<path d="M114.5 63.7l.8 1M114.6 67.7l.8 .9M114.6 64.6h.1M114.6 68.5v.1M114.6 60.8l.9 .9M114.7 64.7l.9 1M114.7 61.6h.1M114.8 68.7l.6 .7M114.8 65.6h.1M114.9 61.8l.8 1M115 65.8l.8 1M115 62.7h.1"/>
<path d="M115 66.7h.1M115.2 62.9l.8 1M115.2 60.6v.1M115.2 66.9l.9 .9M115.2 63.8h.1M115.3 67.7v.1M115.4 63.9l.9 1M115.4 60.8v.1M115.5 67.9l.8 1M115.5 64.8v.1M115.6 68.8v.1M115.6 61l.8 1"/>
<path d="M115.6 65l.9 1M115.6 61.9v.1M115.7 69l.4 .4M115.7 65.9h.1M115.8 62.1l.9 1M115.9 60.6l.3 .3M115.9 66.1l.9 1M115.9 63h.1M116 67h.1M116.1 63.2l.9 1M116.2 67.2l.8 .9M116.2 64.1h.1"/>
<path d="M116.3 68.1h.1M116.3 64.3l.9 .9M116.3 61.2h.1M116.4 68.2l.9 1M116.4 65.1v.1M116.5 69.1v.1M116.5 61.3l.9 1M116.6 60.6l.5 .6M116.6 65.3l.9 1M116.6 62.2v.1M116.7 69.3l.1 .1M116.7 66.2h.1"/>
<path d="M116.8 62.4l.9 1M116.9 66.4l.8 1M116.9 63.3h.1M117 67.3h.1M117 63.5l.9 1M117.1 67.5l.9 1M117.1 64.3v.1M117.2 68.3v.1M117.2 60.6l.9 .9M117.3 64.6l.9 .9M117.3 61.4v.1M117.4 68.5l.8 .9"/>
<path d="M117.4 65.4v.1M117.5 69.4h.1M117.5 61.6l.8 1M117.6 65.6l.8 1M117.6 62.5h.1M117.7 66.5h.1M117.7 62.7l.9 1M117.8 66.7l.9 1M117.8 63.6h.1M117.9 67.6h.1M118 63.8l.9 .9M118 60.7h.1"/>
<path d="M118.1 67.7l.8 1M118.1 64.7h.1M118.2 68.6v.1M118.2 60.8l.8 1M118.3 64.8l.8 1M118.3 61.7h.1M118.3 68.8l.6 .6M118.3 65.7h.1M118.4 61.9l.9 1M118.5 65.9l.9 1M118.5 62.8h.1M118.6 66.8h.1"/>
<path d="M118.6 60.6l.2 .2M118.7 63l.9 .9M118.8 67l.8 .9M118.8 63.9h.1M118.9 67.8v.1M118.9 64.1l.7 .7M118.9 60.9v.1M119 68.1l.6 .6M119 64.9v.1M119.1 68.9h.1M119.1 61.2l.5 .4M119.2 65.1l.4 .4"/>
<path d="M119.2 62h.1M119.3 69.1l.3 .3M119.3 66h.1M119.3 60.6l.3 .3M119.4 62.2l.2 .2M119.5 66.2l.1 .1M119.5 63.1h.1M119.6 67.1h.1M119.6 60.6h-8.7l-.3 .2-.2 .4v7.7l.2 .4 .3 .1h8.7M119.6 60.5h25.4v32.1h-25.4zM132.3 60.7v.2M132.3 61.2v1.4"/>
<path d="M132.3 62.9v.2M132.3 63.4v1.4M132.3 65.1v.2M132.3 65.6v1.4M132.3 67.3v.3M132.3 67.8v1.4M132.3 69.5v.2M132.3 70v1.4M132.3 71.7v.2M132.3 72.2v1.4M132.3 73.9v.2M132.3 74.4v1.4"/>
<path d="M132.3 76.1v.2M132.3 76.6v1.4M132.3 78.3v.2M132.3 78.8v1.4M165.5 68.5l.7 .8M165.5 67.7l.4 .5M165.5 66.9l.2 .3M165.5 64.6l.6 .7M165.5 63.8l.3 .5M165.5 63l.1 .2M165.5 61.5l.8 .9M165.5 65.4l.8 1"/>
<path d="M165.5 62.3v.1M165.6 66.3h.1M165.6 60.8l.4 .5M165.7 62.5l.8 1M165.7 66.5l.9 1M165.7 63.4h.1M165.8 67.4h.1M165.9 63.6l.9 1M166 67.6l.9 .9M166 64.5h.1M166.1 68.5h.1M166.1 60.7l.8 .9"/>
<path d="M166.2 64.7l.8 .9M166.2 61.5v.1M166.3 68.6l.7 .8M166.3 65.5h.1M166.3 61.7l.9 1M166.4 65.7l.9 1M166.4 62.6h.1M166.5 66.6h.1M166.6 62.8l.9 1M166.7 66.8l.9 .9M166.7 63.7h.1M166.8 67.7h.1"/>
<path d="M166.9 63.9l.8 .9M166.9 60.8h.1M166.9 67.8l.9 1M166.9 64.7v.1M167 68.7v.1M167 60.9l.9 1M167.1 64.9l.9 1M167.1 61.8v.1M167.2 68.9l.5 .5M167.2 65.8h.1M167.3 62l.9 1M167.4 66l.9 1"/>
<path d="M167.4 62.9h.1M167.4 60.6l.2 .2M167.5 66.9h.1M167.6 63.1l.8 1M167.6 67.1l.9 1M167.6 63.9v.1M167.7 67.9v.1M167.8 64.2l.9 .9M167.8 61v.1M167.9 68.1l.9 1M167.9 65v.1M168 69h.1"/>
<path d="M168 61.2l.9 1M168.1 65.2l.9 1M168.1 62.1h.1M168.1 60.6l.5 .6M168.2 69.2l.1 .2M168.2 66.1h.1M168.3 62.3l.8 1M168.3 66.3l.9 1M168.3 63.2h.1M168.4 67.2h.1M168.5 63.4l.9 .9M168.6 67.4l.8 .9"/>
<path d="M168.6 64.3h.1M168.7 68.2v.1M168.8 64.5l.8 .9M168.8 61.3v.1M168.8 60.6l.8 .8M168.9 68.5l.8 .9M168.9 65.3v.1M168.9 77.9h9.5M169 69.3h.1M169 61.5l.8 1M169 62.4h.1M169 65.5l.9 1"/>
<path d="M169.1 66.4h.1M169.2 62.6l.9 1M169.3 66.6l.8 1M169.3 63.5h.1M169.4 67.5h.1M169.4 79.5v11.4M169.4 77.9l.2 1.6h-.4zM169.4 63.7l.9 1M169.6 67.7l.8 .9M169.6 64.6h.1M169.6 68.5v.1M169.6 60.8l.9 .9"/>
<path d="M169.7 64.7l.9 1M169.7 61.6h.1M169.8 65.6h.1M169.8 68.7l.6 .7M169.9 61.8l.8 1M170 65.8l.8 1M170 62.7h.1M170.1 66.7h.1M170.1 62.9l.9 1M170.2 60.6l.1 .1M170.3 66.9l.8 .9M170.3 63.8h.1"/>
<path d="M170.3 67.7v.1M170.4 63.9l.9 1M170.4 60.8v.1M170.5 67.9l.9 1M170.5 64.8v.1M170.6 68.8v.1M170.6 61l.8 1M170.7 65l.8 1M170.7 61.9v.1M170.7 69l.4 .4M170.7 65.9h.1M170.8 62.1l.9 1"/>
<path d="M170.9 60.6l.3 .3M170.9 66.1l.9 1M170.9 63h.1M171 67h.1M171.1 63.2l.9 1M171.2 67.2l.9 .9M171.2 64.1h.1M171.3 68.1h.1M171.4 64.3l.8 .9M171.4 61.2h.1M171.4 68.2l.9 1M171.4 65.1v.1"/>
<path d="M171.5 69.1v.1M171.5 61.3l.9 1M171.6 60.6l.5 .6M171.6 65.3l.9 1M171.6 62.2v.1M171.7 69.3l.1 .1M171.7 66.2h.1M171.8 62.4l.9 1M171.9 66.4l.8 1M171.9 63.3h.1M172 67.3h.1M172.1 63.5l.8 1"/>
<path d="M172.1 67.5l.9 1M172.1 64.3v.1M172.2 68.3v.1M172.3 60.6l.8 .9M172.3 64.6l.9 .9M172.3 61.4v.1M172.4 68.5l.8 .9M172.4 65.4v.1M172.5 69.4h.1M172.5 61.6l.9 1M172.6 65.6l.8 1M172.6 62.5h.1"/>
<path d="M172.7 66.5h.1M172.7 62.7l.9 1M172.9 66.7l.8 1M172.9 63.6h.1M172.9 67.6h.1M173 63.8l.9 .9M173 60.7h.1M173.1 67.7l.9 1M173.1 64.7h.1M173.2 68.6v.1M173.2 60.8l.8 1M173.3 64.8l.8 1"/>
<path d="M173.3 61.7h.1M173.4 68.8l.5 .6M173.4 65.7h.1M173.4 61.9l.9 1M173.5 65.9l.9 1M173.5 62.8h.1M173.6 66.8h.1M173.7 60.6l.1 .2M173.7 63l.9 .9M173.8 67l.8 .9M173.8 63.9h.1M173.9 67.8v.1"/>
<path d="M174 64.1l.6 .7M174 60.9v.1M174 68.1l.6 .6M174 64.9v.1M174.1 68.9h.1M174.1 61.2l.5 .4M174.2 65.1l.4 .4M174.2 62h.1M174.3 69.1l.3 .3M174.3 66h.1M174.4 60.6l.2 .3M174.4 62.2l.2 .2"/>
<path d="M174.5 66.2l.1 .1M174.5 63.1h.1M174.6 67.1h.1M174.6 60.6h-8.7l-.3 .2-.1 .4v7.7l.1 .4 .3 .1h8.7M178.8 77.9h.2v3.3h-.2zM178.8 77.9h.1M179.2 77.9h.3v3.3h-.3zM179.7 77.9h.3v3.3h-.3zM180.2 77.9h.3v3.3h-.3zM180.7 77.9h.3v3.3h-.3zM181.2 77.9h.3v3.3h-.3zM181.7 77.9h.3v3.3h-.3z"/>
<path d="M182.2 77.9h.3v3.3h-.3zM182.7 77.9h.3v3.3h-.3zM183.2 77.9h.2v3.3h-.2zM183.6 77.9h.3v3.3h-.3zM184.1 77.9h.3v3.3h-.3zM184.6 77.9h.3v3.3h-.3zM185.1 77.9h.3v3.3h-.3zM185.6 77.9h.3v3.3h-.3zM186.1 77.9h.3v3.3h-.3zM186.6 77.9h.3v3.3h-.3zM187.1 77.9h.3v3.3h-.3zM187.3 60.7v.3"/>
<path d="M187.3 61.3v1.4M187.3 62.9v.3M187.3 63.5v1.4M187.3 65.2v.2M187.3 65.7v1.4M187.3 67.4v.2M187.3 67.9v1.4M187.3 69.5v15.2M187.6 77.9h.2v3.3h-.2zM188 77.9h.3v3.3h-.3zM188.5 77.9h.3v3.3h-.3zM189 77.9h.3v3.3h-.3z"/>
<path d="M189.5 77.9h.3v3.3h-.3zM190 77.9h.3v3.3h-.3zM228.9 62h17.8M228.9 64.7h17.8M228.9 67.5h17.8M228.9 70.3h17.8M228.9 73h17.8M228.9 75.8h17.8M228.9 78.6h17.8M39.3 91.2h.5l-.2 1.4zM39.4 80.9a1.17 1.17 0 0 1 1.9 0M39.4 83.9a1.17 1.17 0 0 0 1.9 0"/>
<path d="M39.4 92.6h16.2M40.5 81.4v.8l.2 .1h.2l.2-.3v-.6h-1.3v.8a.33 .33 0 0 0 .6 0l.1-.2M41.1 82.8h-1.3v.8M43.5 89h12.1M43.5 83.1a1.34 1.34 0 0 0 2.1 0M43.5 87.3h.5l-.2 1.7zM43.8 89h.1M44 81.5h1.3a.74 .74 0 0 1-.4 1 .74 .74 0 0 1-.9-.5zM44.3 81.1a.64 .64 0 0 1-.1-1 .64 .64 0 0 1 1 0 .57 .57 0 0 1-.2 1M45.7 92.6h.1M45.7 93.7v4.5M45.7 92.6l.2 1.1h-.4z"/>
<path d="M46 98.4l.3 .3h-1.2M47.4 87.2h.4l-.2 1.4zM47.4 83a1.19 1.19 0 0 0 2 0M47.5 88.6h8.4M47.6 88.6v.1M47.9 80.6a.67 .67 0 0 1 .8-.2 .67 .67 0 0 1 .5 .6 .64 .64 0 0 1-.9 .4 .64 .64 0 0 1-.4-.8zM49.2 81.8h-1.3v.9M51.6 86.3h.4l-.2 1.4zM51.6 82.8a1.19 1.19 0 0 0 1.9 0M51.6 87.7h5.3M51.8 87.7h.1M52 81.3l1.3 .5-1.3 .6"/>
<path d="M52.5 81.5v.7M55.7 92.3h1.8v.3M55.8 92.6h.1M55.8 93v11.9M55.9 89h25.2M56 89h.8v.9h-.8zM56 89h.2l-.2 .9zM56 89v.9zM56.1 88.6v.1M56.2 89h.4l-.4 .3zM56.2 89.3l.4-.3v.3zM56.2 89.6h.4l-.4 .3z"/>
<path d="M56.2 89.9l.4-.3v.3zM56.2 89v.9h-.2zM56.3 89.5l.1-.2v.2M56.3 89.5h.1M56.6 89h.2l-.2 .9zM56.6 89.4l-.1 .2M56.6 89.4h-.1l.1 .1M56.8 89v.9zM56.8 89v.9h-.2zM57.1 87.7h.1M57.3 88.5l.2 .4-1.1 .6zM58.7 91.2l.3 .1v.1l-.3 .1-.1-.1z"/>
<path d="M58.8 92.3h19.5M58.9 90.4h.1v.2M59 91h.1v.7h-.1zM59.1 91h.1v.7h-.1zM59.3 91h.1v.7h-.1zM59.4 91h.1v.7h-.1zM59.5 91h.2v.7h-.2zM59.7 91h.1v.7h-.1zM59.8 91h.2v.7h-.2zM60 91h.1v.7h-.1zM60.1 91h.1v.7h-.1zM60.3 91h.1v.7h-.1z"/>
<path d="M60.4 91h.1v.7h-.1zM60.6 91v.7zM60.7 91h.1v.7h-.1zM60.8 91h.1v.7h-.1zM61 91h.1v.7h-.1zM61.1 91h.1v.7h-.1zM61.2 89.7h14.7v.7h-14.7zM61.3 91h.1v.7h-.1zM61.4 91h.1v.7h-.1zM61.6 91h.1v.7h-.1zM61.7 91h.1v.7h-.1zM61.8 91h.1v.7h-.1z"/>
<path d="M62 91h.1v.7h-.1zM62.1 91h.1v.7h-.1zM62.3 91h.1v.7h-.1zM62.4 91h.1v.7h-.1zM62.6 91h.1v.7h-.1zM62.7 91h.1v.7h-.1zM62.9 91v.7zM63 91h.1v.7h-.1zM63.1 91h.1v.7h-.1zM63.3 91h.1v.7h-.1zM63.4 91h.1v.7h-.1zM63.6 91h.1v.7h-.1z"/>
<path d="M63.7 91h.1v.7h-.1zM63.8 91h.2v.7h-.2zM64 91h.1v.7h-.1zM64.1 91h.1v.7h-.1zM64.3 91h.1v.7h-.1zM64.4 91h.1v.7h-.1zM64.5 91h.2v.7h-.2zM64.7 91h.1v.7h-.1zM64.8 91h.1v.7h-.1zM65 91h.1v.7h-.1zM65.1 91h.1v.7h-.1zM65.2 98.2h13.5l.4 .1 .1 .4v1.7l-.1 1.2-.5 1.1-.8 .8-.3 .8v4.6"/>
<path d="M65.3 91h.1v.7h-.1zM65.4 91h.1v.7h-.1zM65.6 91v.7zM65.7 91h.1v.7h-.1zM65.8 91h.1v.7h-.1zM66 91h.1v.7h-.1zM66.1 91h.1v.7h-.1zM66.3 91h.1v.7h-.1zM66.4 91h.1v.7h-.1zM66.6 91h.1v.7h-.1zM66.6 84.7v.8M66.7 84l-.3 .9"/>
<path d="M66.7 91h.1v.7h-.1zM66.7 84.4h-.1M66.7 84.6l-.2 .1M66.7 85h-.3M66.8 85.2l-.2 .3M66.9 91v.7zM66.9 84.1v1.5M66.9 84.8l.4 .8M67 91h.1v.7h-.1zM67 85.3l-.1 .3M67.1 84.5h-.2M67.1 91h.1v.7h-.1z"/>
<path d="M67.1 84.2h-.2M67.1 84.1v.6l-.2 .1M67.2 84.9l-.1 .2M67.3 91h.1v.7h-.1zM67.4 91h.1v.7h-.1zM67.6 91h.1v.7h-.1zM67.6 84.2l.1 .2M67.7 91h.1v.7h-.1zM67.8 91h.2v.7h-.2zM67.8 84.5l-.2 .3M67.8 84v.9M67.9 85.1l-.3 .1"/>
<path d="M67.9 85.1l-.4 .6M68 91h.1v.7h-.1zM68 85.1l.4 .5h.1M68 84.8v.9l-.2-.2M68 84.4l.2 .2M68.1 91h.1v.7h-.1zM68.2 84l-.2 .6M68.3 91h.1v.7h-.1zM68.3 84.9l-.2 .3M68.4 84.2l-.3 .1M68.4 84.2l-.3 .7M68.4 91h.1v.7h-.1z"/>
<path d="M68.5 80v.3M68.5 80.6v1.4M68.5 82.3v.2M68.5 82.8v1.4M68.5 84.4v.3M68.5 85v1.4M68.5 86.6v.3M68.5 87.2v20.2M68.6 91h.1v.7h-.1zM68.7 91h.1v.7h-.1zM68.8 85.2l-.1 .5M68.9 91v.7z"/>
<path d="M68.9 84.5v.7M69 91h.1v.7h-.1zM69 85.3l.1 .3M69.1 91h.1v.7h-.1zM69.1 84v.6M69.2 85.3l.1 .3M69.3 91h.1v.7h-.1zM69.3 84.6v.5h-.4M69.3 84.6l-.4 .1M69.3 85.2l.2 .5M69.4 91h.1v.7h-.1zM69.5 84.3h-.4"/>
<path d="M69.5 91h.2v.7h-.2zM69.7 91h.1v.7h-.1zM69.9 91h.1v.7h-.1zM70 91h.1v.7h-.1zM70.1 91h.1v.7h-.1zM70.3 91h.1v.7h-.1zM70.4 91h.1v.7h-.1zM70.6 91v.7zM70.7 91h.1v.7h-.1zM70.8 91h.1v.7h-.1zM71 91h.1v.7h-.1zM71.1 91h.1v.7h-.1z"/>
<path d="M71.3 91h.1v.7h-.1zM71.4 91h.1v.7h-.1zM71.6 91h.1v.7h-.1zM71.7 91h.1v.7h-.1zM71.8 91h.1v.7h-.1zM72 91h.1v.7h-.1zM72.1 91h.1v.7h-.1zM72.3 91h.1v.7h-.1zM72.4 91h.1v.7h-.1zM72.6 91h.1v.7h-.1zM72.7 91h.1v.7h-.1zM72.8 91h.1v.7h-.1z"/>
<path d="M73 91h.1v.7h-.1zM73.1 91h.1v.7h-.1zM73.3 91h.1v.7h-.1zM73.4 91h.1v.7h-.1zM73.6 91h.1v.7h-.1zM73.7 91h.1v.7h-.1zM73.9 91v.7zM74 91h.1v.7h-.1zM74.1 91h.1v.7h-.1zM74.3 91h.1v.7h-.1zM74.4 91h.1v.7h-.1zM74.5 91h.2v.7h-.2z"/>
<path d="M74.7 91h.1v.7h-.1zM74.9 91h.1v.7h-.1zM75 91h.1v.7h-.1zM75.1 91h.1v.7h-.1zM75.3 91h.1v.7h-.1zM75.4 91h.1v.7h-.1zM75.6 91v.7zM75.7 91h.1v.7h-.1zM75.8 91h.2v.7h-.2zM76 91h.1v.7h-.1zM76.1 91h.1v.7h-.1zM76.3 91h.1v.7h-.1z"/>
<path d="M76.4 91h.1v.7h-.1zM76.5 91h.2v.7h-.2zM76.7 91h.1v.7h-.1zM76.8 91h.1v.7h-.1zM77 91h.1v.7h-.1zM77.1 91h.1v.7h-.1zM77.3 91h.1v.7h-.1zM77.4 92.6v5.6M77.4 91h.1v.7h-.1zM77.6 91v.7zM77.7 91h.1v.7h-.1zM77.8 91h.1v.7h-.1z"/>
<path d="M78 90.4v.2M78 91h.1v.7h-.1zM78.1 91.3l.3-.1 .1 .2-.2 .1zM78.2 90.4h.1v.2l-.2-.1M78.4 90.5h-.1l.1-.1v.2M78.8 91v.4l-.3 .7-.7 .4a2.43 2.43 0 0 0-2.7 2.1 3.1 3.1 0 0 0 1.8 3.6M79.1 92.6v5.7M79.8 88.2l-2-2.3h-16.7l-3.7 2.8M80 88.1l.7 1.1-1.1-.8zM80.3 89h.8v.9h-.8zM80.3 89h.2l-.2 .9zM80.3 89v.9z"/>
<path d="M80.5 89.4v.2M80.5 89.4h.1l-.1 .1M80.5 89h.3l-.3 .3zM80.5 89.3l.3-.3v.3zM80.5 89.6h.3l-.3 .3zM80.5 89.9l.3-.3v.3zM80.5 89v.9h-.2zM80.6 89.5l.1-.2 .1 .2M80.7 89.5h.1M80.8 89h.3l-.3 .9zM81.1 89v.9zM81.1 89v.9h-.3z"/>
<path d="M81.1 91h-22.8v.4l.3 .7 .6 .4h1l4.7 3.6 .3 .3v21.9M81.3 88.4h-.1v-27.8h-25.4v28.1h-.1M81.3 92.3h-1.8v.3M93.8 89.4h1.2M95 89.2l1.3 .2-1.3 .3zM96.3 89.3v2.5M96.4 90.5h.2v18.5h-.2zM96.4 95.8l.2 .1v.7h-.2zM96.7 88.4h.2M96.9 92.1h.8M97 92.6h.2v1.4h-.2zM97 94h.2l-.6 1.9-.2-.1z"/>
<path d="M97.6 89.3v2.5M97.6 92v.1M97.6 89.4l1.2-.2v.5zM97.7 89.4l-.2 .1-.1 .2 .1 .3 .2 .1M97.7 82.8l-.2 .1-.1 .3 .1 .2 .2 .1M98.8 89.4h5.2v8.2M104.2 94.2h.9M104.2 97h.9M104.2 97.5l.9 .8M104.3 93a.76 .76 0 0 1 1.2 .3 .66 .66 0 0 1-.6 .5 .66 .66 0 0 1-.7-.5zM104.3 90.8v.1M104.4 97a.45 .45 0 0 1-.1-.6 .45 .45 0 0 1 .7 0 .45 .45 0 0 1-.1 .6"/>
<path d="M104.5 91.5a.48 .48 0 0 0-.3 .7 .48 .48 0 0 0 .8 .1v-.4l.5 .5v-.8M104.8 94.2a.43 .43 0 0 1 0 .8h-.6M104.8 95a.5 .5 0 0 1 .2 .6l-.8 .1M105.1 97.5l-.9 .8M105.2 89.7l.3 .3h-1.3M121.8 98.3h2.9v3.1h-2.9zM121.8 92.6v5.7M121.8 99.6l1.5 1.8M121.8 99.2l1.9 2.2M121.8 98.8l2.2 2.6M121.8 98.4l2.6 3M122 98.3l-.2 .2"/>
<path d="M122.1 98.3l2.6 3.1M122.1 98.3h.4v3.1h-.4zM122.4 98.3l-.6 .6M122.4 98.3l2.3 2.7M122.7 98.3l-.9 1M122.8 98.3l1.9 2.3M122.8 98.3h.4v3.1h-.4zM123 98.3l-1.2 1.4M123.1 98.3l1.6 1.9M123.4 98.3l-1.6 1.8M123.5 98.3l1.2 1.5M123.5 92.6v5.6"/>
<path d="M123.7 98.3l-1.9 2.2M123.8 98.3l.9 1.1M124.1 98.3l-2.3 2.6M124.1 92.6a3.1 3.1 0 0 1 1.7 2.8 3.1 3.1 0 0 1-1.8 2.8M124.1 98.3l.6 .7M124.4 98.3l-2.6 2.9M124.5 98.3l.2 .3M124.7 98.3l-2.6 3.1M124.7 98.7l-2.3 2.7M124.7 99.1l-1.9 2.3M124.7 99.5l-1.6 1.9M124.7 99.9l-1.2 1.5"/>
<path d="M132.3 80.5v.3M132.3 81v1.4M132.3 82.7v.3M132.3 83.2v1.4M132.3 84.9v.3M132.3 85.4v1.4M132.3 87.1v.2M132.3 87.6v1.4M132.3 89.3v.2M132.3 89.8v1.4M132.3 91.5v.2M132.3 92v1.4"/>
<path d="M132.3 93.7v.3M132.3 94.2v1.4M132.3 95.9v.3M132.3 96.4v1.4M132.3 98.1v.2M132.3 98.6v1.4M135.6 98.2h-13.5l-.3 .2-.1 .3v1.8l.1 1.2 .5 1 1 1.2 .1 4.9 .2 .2h16.1v2.6M140.6 92.6l-4.7 3.5-.2 .3-.1 .5v11.9v.2h-.2M168.9 92.6h5.3M169.2 90.9h.4l-.2 1.7zM169.4 92.6h.1M174.6 92.6v-32.1h25.5v32.1"/>
<path d="M174.6 92.6h25.5M176.8 88.7v4.4h1.7v-4.4M177.7 93.7l.7 1.1-.3 .3zM179 88.7a3.2 3.2 0 0 1 1.5 4.4h13.5l-3.1-2.3-.2-.3-.1-12.6h-.2h-11.8l-.2 .2v4.9l-1.1 1.2-.5 1-.2 1.2v1.7l.2 .4 .4 .2h13.4M179.1 83.6l.3-.2 .3 .2 .1 .3-.1 .3-.3 .1-.3-.1-.1-.3zM179.2 99.8v.3M179.2 99.3l-.2 .4M179.3 99.2v.3M179.4 99v.2M179.5 99.2v.3M179.5 99.3l.2 .3M179.5 99.6h-.3"/>
<path d="M179.6 99.5l-.1 .3h-.3M179.6 100h-.4M179.6 99.9l-.1 .5-.2-.2M179.7 99.2l-.6 .1M180.1 99.1v1.3l-.2-.2M180.2 99.6l-.3 .2M180.2 99.4l-.3 .1M180.3 99.2l-.2 1.2M180.5 99.6v.8M180.6 99.1l-.3 .2M180.6 99.6l-.3 .1M180.9 99.2v.3"/>
<path d="M181.1 99.3l-.2 .5M181.2 99.6l-.3 .8M181.2 99.8l.2 .6h.1M181.2 99v.2M181.2 99.6l.1 .2M181.2 99.4l.2 .2M181.4 99.2l-.5 .1M181.5 99.8l-.6 .1M181.5 99.2l-.1 .2M181.8 99.9v.5M181.8 99.3v.5M181.8 99.7h.5"/>
<path d="M182.1 99.1v1.2M182.3 99.3v.5M182.3 99.9v.5M182.8 99.8l.3-.1v.7l-.1-.1M182.8 99.7v.7M182.9 99.1v.6M182.9 99.5l-.3 .1M182.9 99.3h-.2M183 99.1l.1 .5h.3l-.1-.2M183.1 99.9l-.3 .1M183.2 99.2l-.2 .2M183.7 99.2v.3"/>
<path d="M183.8 99.6l-.1 .4-.2 .4M183.9 99.1v.5M183.9 99.6l.1 .8h.2v-.3M184.1 99.2l-.2 .3M184.2 99.6l-.7 .1M184.5 99.8l-.1 .6M184.5 99.8h.1M184.5 99.2v.6M184.6 99.5l-.1 .1M184.6 99.2v1.2l-.1-.1M184.6 99.3h-.1M184.8 99.8l.3 .6"/>
<path d="M184.8 99.5l-.1 .3M184.9 99.1v.2M185 99.7l-.3 .7M185 99.5l.1 .3M185.1 99.4h-.4M185.4 99v1.4M185.4 99.5l-.1 .6M185.4 99.6l.2 .1M185.6 99.5h-.3M185.6 99.1v1.2h.4M185.8 99.4v.6M186 99.4h-.3"/>
<path d="M186 99.7h-.3M186 99.1l-.4 .1M186 100h-.3M187.3 84.9v.3M187.3 85.5v1.4M187.3 87.1v.3M187.3 87.7v1.4M187.3 89.4v.2M187.3 89.9v1.4M187.3 91.5v.3M187.3 92.1v1.4M187.3 93.7v.3"/>
<path d="M187.3 94.3v1.4M187.3 95.9v.3M187.3 96.5v1.4M187.3 98.1v.3M187.3 98.7v1.4M189.4 83.6l.3-.2 .3 .2v.3v.3l-.3 .1-.3-.1-.1-.3zM191.5 94.6l1-.9-.6 1.2zM191.7 94.8l-2.2 2.9h-10l-1.2-2.8M195 93.1v.1M195.1 93.1h9.9M200.2 92.6h4.8M204.7 91.1h.4l-.2 1.5z"/>
<path d="M204.9 82.3v8.8M204.9 92.6h.1M204.9 94.5v1.5M204.9 93.1l.2 1.4h-.4zM205.1 85.9h.9M205.1 88.8h.9M205.1 89.3l.9 .7M205.2 82.7a1.05 1.05 0 0 1 1.2 0 .52 .52 0 0 1-.2 .7 .63 .63 0 0 1-.8 0 .63 .63 0 0 1-.2-.7zM205.3 83.9h-.1v.1M205.3 84.6l.2-.1 .2 .2 .2 .6a.28 .28 0 0 0 .5 .1 .56 .56 0 0 0-.2-.8l-.2 .1-.1 .1a.53 .53 0 0 1-.5 .7l-.1-.1a.64 .64 0 0 1 0-.8zM205.3 88.8l-.2-.4 .1-.3 .5-.1 .2 .1 .1 .3-.2 .4M205.7 85.9l.3 .4-.1 .3-.8 .1"/>
<path d="M205.7 86.7l.3 .3-.1 .3-.8 .1M206 89.3l-.9 .7M228.9 89.7h17.8M228.9 81.4h17.8M228.9 84.2h17.8M228.9 86.9h17.8M228.9 92.4h17.8M228.9 95.2h17.8M228.9 98h17.8M45.1 100.1h1.2l-.8-.7v.9M45.2 100.7h-.1l.1 .1M45.3 101.4l-.2 .3a.62 .62 0 0 0 .6 .4 .62 .62 0 0 0 .6-.4l-.2-.3a.4 .4 0 0 0-.6 .2 .4 .4 0 0 0 .4 .5"/>
<path d="M45.3 102.6a.45 .45 0 0 0-.2 .5 .45 .45 0 0 0 .6 .3l.1-.4 .5 .4v-.7M45.5 107.9h.4l-.2 1.1zM45.7 103.4v4.5M55.8 104.3l1.5-.3v.6zM57.3 104.3h6.5M59.5 115.8a.59 .59 0 0 1 .7-.2 .59 .59 0 0 1 .3 .7 .6 .6 0 0 1-.7 .2 .6 .6 0 0 1-.3-.7zM59.5 114.3v1.1M59.5 117v-.1v.1M59.6 114.9h1M59.7 113a.41 .41 0 0 0-.2 .7 .41 .41 0 0 0 .6-.1v-.2l.5 .4v-.7M59.7 117.5a.42 .42 0 0 0-.2 .7 .42 .42 0 0 0 .6 0v-.2l.5 .3v-.7M59.8 107.9h.3l-.1 1.1z"/>
<path d="M60 106.8v1.1M60 109v3.8M60 105.7l.1 1.1h-.3zM60.1 114.3v1.1M63.8 104l1.4 .3-1.4 .3zM64.8 113.9h1M65.2 108.8l.2 .2M65.2 118.3l1-.2v.4zM65.6 105.7h.3v3.3h-.3zM65.8 108.2h.1M65.8 109.2v6.8M65.8 105.7l-5.8 .1"/>
<path d="M65.8 113.7l.9 .2-.9 .2zM65.8 116l.9-.2v.4zM66 102.7l.2-.2 .3 .2 .1 .3-.1 .3-.3 .1-.2-.1-.2-.3zM66.1 105.7h.3v3.3h-.3zM66.1 109v.1M66.1 111.2h1M66.2 118.3h1.8M66.6 105.7h.3v3.3h-.3zM66.6 109v.1M66.7 105.7v.1M66.7 108.2h.1M66.7 109.2v4.7h.5"/>
<path d="M66.7 116h.7M67.1 105.7h.2v3.3h-.2zM67.1 111.1l.9 .1-.9 .2zM67.2 108.2h.1M67.2 109.2v4.8M67.2 113.9l1-.2v.4zM67.5 105.7h.3v3.3h-.3zM67.6 115.6l.3-.3v1.4M68 105.7h.3v3.3h-.3zM68 107.8v.1M68 108.9v2.3h.3M68.1 117.9l.3-.3v1.4"/>
<path d="M68.2 113.9h1M68.3 107.8v.1M68.3 108.9v2.4M68.3 111.2l1-.1v.3zM68.5 105.7h.3v3.3h-.3zM68.5 115.6l.3-.3v1.4M69 105.7h.3v3.3h-.3zM69.1 118l.1-.3h.4l.1 .1v.3l-.2 .3-.5 .6h.8M69.3 111.2h1M69.4 113.4l.1-.1a.62 .62 0 0 1 .1 1.1h-.1a.6 .6 0 0 1-.2-.8zM69.5 116.5v.2v-.1M69.5 105.7h.3v3.3h-.3z"/>
<path d="M70 105.7h.3v3.3h-.3zM70.2 118.8l-.1 .1h.2M70.2 114.3v.1h.1M70.5 105.7h.3v3.3h-.3zM70.5 110.7a.34 .34 0 0 1 .5 .2v.3a.47 .47 0 0 1-.3 .6h-.1a.82 .82 0 0 1-.1-1.1zM70.6 115.3h-.5l-.1 .6 .6-.1 .2 .4-.1 .3-.2 .2h-.3l-.2-.3M70.8 115.9h1M70.8 116.6h1M71 105.7h.3v3.3h-.3zM71.2 113.3h-.5v.5a.35 .35 0 0 1 .5 0 .35 .35 0 0 1-.1 .6 .35 .35 0 0 1-.5-.2M71.3 115.3v1.2M71.4 111.7v.1v-.1"/>
<path d="M71.4 117.6h-.6v.6a.42 .42 0 0 1 .6 0 .42 .42 0 0 1-.1 .6 .42 .42 0 0 1-.6-.1M71.4 113.8h.8M71.4 114.4h.8M71.5 105.7h.2v3.3h-.2zM71.7 118.9h1M71.7 118.2h1M71.8 113.3v1M71.9 110.7h.5l-.3 .4a.34 .34 0 0 1 .3 .6 .34 .34 0 0 1-.6-.1M71.9 105.7h.3v3.3h-.3zM72.1 115.4l.3-.1a.58 .58 0 0 1 .3 .8l-.1 .5-.3 .1a.91 .91 0 0 1-.2-1.3zM72.2 117.6v1.2M72.4 105.7h.3v3.3h-.3z"/>
<path d="M72.5 113.4l.2-.1a.78 .78 0 0 1 .2 1.1h-.3a.67 .67 0 0 1-.1-1zM72.5 111.2h.8M72.5 111.7h.8M72.9 110.7v1M72.9 105.7h.3v3.3h-.3zM73 117.7a.36 .36 0 0 1 .6 .2v.3a.61 .61 0 0 1-.3 .8h-.1a.87 .87 0 0 1-.2-1.3zM73.1 116.5v.2l.1-.1M73.3 114.3l.1 .1M73.4 105.7h.3v3.3h-.3zM73.6 110.7h.3a.62 .62 0 0 1-.1 1.1l-.3-.5zM73.8 115.4l.3-.1a.77 .77 0 0 1-.2 1.4 .97 .97 0 0 1-.1-1.3zM73.9 113.4l.1-.1a.63 .63 0 0 1 .1 1.1h-.1a.6 .6 0 0 1-.2-.8z"/>
<path d="M73.9 105.7h.3v3.3h-.3zM74 118.8l-.1 .1h.2M74.4 105.7h.3v3.3h-.3zM74.5 111.7v.1v-.1M74.5 117.9l.3-.3v1.4M74.8 113.3h.5l-.3 .5h.3v.5l-.4 .1-.2-.2M74.8 118.3h1.7M74.9 105.7h.3v3.3h-.3zM75 110.7h.2a.64 .64 0 0 1 0 1.1 .79 .79 0 0 1-.2-1.1zM75.3 116h.7M75.4 105.7h.3v3.3h-.3zM75.4 115.3h-.5l-.1 .6 .2-.1a.37 .37 0 0 1 .4 .1 .37 .37 0 0 1 .1 .4l-.1 .3-.3 .1-.2-.1-.2-.2"/>
<path d="M75.9 105.7h.2v3.3h-.2zM75.9 110.7h.5l-.3 .4 .3 .1v.5a.35 .35 0 0 1-.6-.1M76 115.8l1 .2-1 .2zM76.3 102.6l.2-.1 .3 .1 .1 .3-.1 .4-.3 .1-.3-.1-.1-.4zM76.3 105.7h.4v3.3h-.4zM76.5 118.1l1 .2-1 .2zM76.8 105.7h.3v3.3h-.3zM77 108.2h.1M77 109.2v6.8M77.5 108.9v9.4M77.6 108.8l1.1-.2v.4zM77.6 108.9l-.1-.1-.2 .2h-31.6"/>
<path d="M78.7 108.8h.9M79.8 108.8l.7-.1 .1-.2-.1-.2-.7-.1v1.3M80.2 108.8l.4 .7M81.2 108.2a.34 .34 0 0 1 .5 .2 .66 .66 0 0 1-.4 1.1 .84 .84 0 0 1-.1-1.3zM82.2 109.3v.1M82.7 108.5l.1-.2 .2-.1 .3 .1a.38 .38 0 0 1-.1 .5l-.5 .7h.8M94.5 112.7h1M95.5 112.5l.9 .2-.9 .2zM96.4 105.7h.1M96.4 106.8v5.9h.3M96.5 104.6h.2v4.4h-.2zM96.7 105.7v.1"/>
<path d="M96.7 106.8v5.9M96.7 112.7l1-.2v.4zM97.7 112.7h1M99 110.8a.44 .44 0 0 1 .6 .2 .66 .66 0 0 1-.4 1 .72 .72 0 0 1-.2-1zM100.1 111.9v.1M100.5 113.8h.6l.1-.1v-.5l-.7-.1v1.3M100.7 110.7h.6l-.3 .5a.4 .4 0 0 1 .3 .7 .4 .4 0 0 1-.7-.1M101.4 111.3h1.1M101.4 112h1.1M101.7 113.1v1.3M101.9 110.7v1.1M102.8 110.8a.4 .4 0 0 1 .5 .2l.1 .3a.6 .6 0 0 1-.4 .7 .86 .86 0 0 1-.2-1.2z"/>
<path d="M103.8 111.9l-.1 .1h.1M104.5 110.8a.45 .45 0 0 1 .5 .2v.8a.38 .38 0 0 1-.3 .2 .38 .38 0 0 1-.4-.2v-.5zM106.1 110.7h-.6v.6l.2-.1h.3l.2 .2v.3a.42 .42 0 0 1-.3 .3 .42 .42 0 0 1-.5-.2M121.8 101.2l.2 .2M121.8 100.8l.6 .6M121.8 100.4l.9 1M121.8 100l1.2 1.4M122.2 101.5v.5M122.3 101.7l.2 .3M122.5 101.5l-.3 .4M122.8 102l.1-.5 .2 .5M122.8 101.9h.3"/>
<path d="M123.2 100.4h.8v.2h-.8zM123.4 104.6h12.2M123.4 105.7l13.3 .1M123.4 105.7h12.2l-12.2 .1zM123.4 105.8l12.2-.1v.1zM123.4 105.7v.1zM123.8 104.6l-.4 .5M123.9 104.6l1.1 1.2M124.1 102.7l.3-.2 .2 .2 .2 .3-.2 .3-.2 .1-.3-.1-.1-.3zM124.7 100.3l-.9 1.1M124.7 100.7l-.6 .7M124.7 101.1l-.2 .3"/>
<path d="M124.9 104.6l-1.5 1.7M125.2 104.9l1.4 1.5M125.8 106.7l1.4 1.6M126 104.6l-2.6 2.9M126.9 105.5l1.3 1.6M127.1 104.6l-3.7 4.2M127.2 104.6l.5 .6M127.4 107.4l1.4 1.5M128.2 104.6l-3.9 4.4M128.3 104.6l1 1.2M128.5 106.1l1.4 1.6M129.1 108l.9 1"/>
<path d="M129.3 104.6l-3.9 4.4M129.6 104.9l1.4 1.5M130.2 106.7l1.3 1.6M130.4 104.6l-3.9 4.4M130.7 108.6l.4 .4M131.3 105.5l1.3 1.6M131.5 104.6l-3.9 4.4M131.6 104.6l.5 .6M131.8 107.4l1.4 1.5M132.3 100.3v.2M132.3 100.8v1.4M132.3 102.5v.2"/>
<path d="M132.3 103v1.4M132.3 104.7v.2M132.3 105.2v1.4M132.3 106.9v.3M132.3 107.4v1.4M132.3 109.1v.2M132.3 109.6v1.4M132.3 111.3v.2M132.3 111.8v1.4M132.3 113.5v.2M132.3 114v1.5M132.6 104.6l-3.9 4.4"/>
<path d="M132.7 104.6l1 1.2M132.9 106.1l1.4 1.6M133.4 108l1 1M133.7 104.6l-3.9 4.4M134 104.9l1.4 1.5M134.2 105.7v.1M134.4 102.7l.2-.2 .3 .2 .2 .3-.2 .3-.3 .1-.2-.1-.2-.3zM134.4 109v.1M134.5 106.7l1.1 1.2M134.6 109v.1M134.8 104.6v.1M134.8 104.6l-3.9 4.4"/>
<path d="M135.1 108.6l.4 .4M135.6 104.9l-3.6 4.1M135.6 106.2l-2.5 2.8M135.6 107.4l-1.4 1.6M135.6 108.6l-.3 .4M135.6 105.7v.1zM135.7 104.6h4M136.2 114.7a.64 .64 0 0 1 .6-.2 .64 .64 0 0 1 .5 .6 .68 .68 0 0 1-1.2 0zM136.2 113.2v1.1M136.2 115.9v-.1v.1M136.3 113.8h1M136.3 111.9a.44 .44 0 0 0-.2 .6 .44 .44 0 0 0 .7 .1v-.3l.5 .4v-.7"/>
<path d="M136.3 116.4a.42 .42 0 0 0-.1 .7 .42 .42 0 0 0 .6 0v-.2l.5 .3v-.7M136.6 107.9h.3l-.2 1.1zM136.7 106.8v1.1M136.7 109v2.7M136.7 105.7l.2 1.1h-.3zM136.8 113.2v1.1M139.1 112.4h1.2l-.8-.6v1M139.1 117.6h1.2l-.1 .7a.29 .29 0 0 1-.5 0l-.1-.7M139.1 118.9h1.2M139.1 114.6a.69 .69 0 0 1 1.2 .3 .6 .6 0 0 1-.6 .4 .6 .6 0 0 1-.6-.4zM139.1 113.1v1.2M139.2 115.8l-.1-.1v.1"/>
<path d="M139.3 113.7h1M139.3 116.3a.48 .48 0 0 0-.2 .6 .48 .48 0 0 0 .4 .3l.2-.1 .1-.3 .5 .3v-.6M139.5 107.9h.3l-.1 1.1zM139.7 105.7v2.2M139.7 104.6l.1 1.1h-.3zM139.7 113.1v1.2M173 115.7h30.9M173 114.1h30.9M175.7 103.8l.2 .2M175.9 104.2l-.2 .1M175.9 104.2l-.1 .7M175.9 102.3h.3"/>
<path d="M175.9 102v.7M175.9 104.6l-.1 .3M176 101.4v.6M176 101.8l-.3 .2M176 101.6l-.3 .1M176 104.3v.7M176.1 101.4v.5h.3v-.2M176.2 102.4h-.3M176.2 103.7v.5M176.2 102v.7l-.1-.1M176.2 102.1h-.3M176.2 104.5h-.2"/>
<path d="M176.2 104.7h-.2M176.3 104.3v.7l-.1-.1M176.3 104.3l-.3 .1M176.3 101.5l-.2 .2M176.3 104l-.3 .1M176.4 103.9h-.4M176.4 104.2h-.5M176.6 104.2l.1 .2M176.7 103.9l.1 .1M176.7 101.6l.1 .2M176.8 104.2l-.1 .8-.1-.1M176.9 102l-.3 .7"/>
<path d="M177 101.4v.5M177 103.7l.1 .3M177.1 104v.9M177.2 101.5l-.2 .4v.7l.3 .1M177.3 104.5h-.4M177.3 101.9l-.7 .1M177.3 102.4v.3M177.3 104l-.4 .1M177.3 104.9l-.5 .1M177.5 101.7l.1 .3M177.6 104.6l-.1 .4M177.7 102.2l.1 .2"/>
<path d="M177.7 104.2v.4M177.7 104.6h.3M177.7 101.4v.8l-.2 .5M177.7 104.7l.1 .2 .3 .2v-.3M177.7 103.9l.1 .2M177.8 101.7l-.1 .2M177.8 103.7l.1 .2M177.8 104.6l.1 .3M177.9 103.9v.2M178 104.4l-.3 .1M178 104.3h-.3M178 101.6v1.1l-.1-.2"/>
<path d="M178 104.2v.4M178.1 104.6l.1 .3M178.1 103.8l-.5 .1M178.2 101.5l-.4 .1M178.2 104.1l-.7 .1M178.5 101.4l-.1 .5M178.6 101.8l-.2 .1M178.6 104.1l-.2 .6M178.6 104.2l.1 .2M178.6 103.7v1.3M178.6 102.1l-.2 .1M178.6 101.7l-.2 .5"/>
<path d="M178.7 102.3l-.3 .2M178.7 104.1h-.3M178.8 101.4v.7l.3 .6v-.3M178.8 103.8l-.1 1.2M178.9 101.5l.1 .1M179 103.8v1.1h.1v-.3M179 103.9h-.2M179 102.1l-.4 .5M179 101.7l-.3 .1M179 101.9l-.3 .2M179.4 102l.5 .7h.1M179.4 104.2l-.1 .3"/>
<path d="M179.5 101.5l-.2 .8M179.5 104.4v.6h-.2M179.6 101.9h-.2M179.6 101.8l-.3 .9M179.7 103.7v.4M179.7 104.4l.1 .6h.2l-.1-.3M179.7 104.5h-.2M179.8 101.4v1M179.8 101.9l.2 .3M179.9 104.1l-.4 .1M179.9 103.9l-.5 .1M179.9 104.3h-.5"/>
<path d="M179.9 104.2v.3M180.3 102v.7M180.3 103.9l.1 .2M180.3 104.8l.7 .2M180.4 104.3h-.2M180.4 104.3l-.1 .5h-.1M180.4 101.6v.4M180.4 102.2v.3M180.5 103.8l-.1 .9M180.5 101.4l.1 .1M180.5 104.3v.4M180.6 104.2h-.1"/>
<path d="M180.6 103.8v.4M180.6 103.9h-.1M180.6 104.6l-.1 .1M180.6 104.3v.3M180.6 104.4h-.1M180.7 102.2l-.1 .2M180.7 101.7h-.3M180.7 102.4l-.3 .1M180.7 102.2h-.3M180.7 104.1v.2M180.7 101.6v.3h-.3M180.7 103.7l.1 .2"/>
<path d="M180.8 104.3v.6M180.8 102l-.5 .1M180.8 104v.3M180.9 102l-.1 .7-.1-.2M180.9 101.5l-.7 .1M180.9 103.9l-.3 .1M180.9 104.5l-.2 .1M180.9 104.3h-.2M181.2 103.9v.3M181.3 101.6l-.2 1.1M181.4 102.3l.5 .5M181.4 104.1l-.2 .4"/>
<path d="M181.4 103.7l.1 .2M181.4 101.7v.4M181.5 104.5l-.1 .4M181.5 101.4l.1 .2M181.5 104.1l.2 .3M181.7 102.1h-.3M181.7 101.7l-.1 .4M181.7 104.5l-.5 .1M181.7 102.2l-.2 .3-.3 .3M181.7 102.2l-.3 .1M181.7 103.9v.2M181.7 103.9l-.5 .1"/>
<path d="M181.8 104.9l-.7 .1M181.8 101.6l-.5 .1M181.8 101.9h-.5M182.3 100.3h-.5M182.7 101.5l-.2 .5 .2 .6M183.1 100.1h-.3M184 101.9h1.1M184 102.2h1.1M185.8 101.3h.2a.79 .79 0 0 1 .3 1.1 .37 .37 0 0 1-.3 .2 .37 .37 0 0 1-.4-.2 1.19 1.19 0 0 1 .2-1.1zM186.8 102.5v.1h.1M187.3 100.4v.2M187.3 100.9v1.4"/>
<path d="M187.3 102.6v.2M187.3 103.1v1.4M187.3 104.8v.2M187.3 105.3v1.5M188.2 102.2h-.9l.6-1v1.4M189.2 101.2h-.6v.7a.44 .44 0 0 1 .6 0 .44 .44 0 0 1 0 .6 .44 .44 0 0 1-.7-.1M193.1 101.5l.1 .5-.2 .6M228.9 114.6h17.8M228.9 117.4h17.8M228.9 100.8h17.8M228.9 103.5h17.8M228.9 106.3h17.8"/>
<path d="M228.9 109.1h17.8M228.9 111.9h17.8M133.5 139.1l.4-.3-.2 .5zM133.6 139.2l-.7 .8M134.4 139.1l.4-.3-.3 .5zM134.4 139.2l-.7 .8M228.9 122.9h17.8M228.9 120.2h17.8M246.7 125.7h-17.8v-69.9h17.8v70.6M37 157.7l.2-.3h.4l.3 .3v.2l-.3 .3h-.4l-.2 .3v.5h.9M37.2 155.1l.2-.3v1.6M37.2 156.4h.5"/>
<path d="M37.8 151.4v1.6l-1-1.6v1.6M38.1 156.2v.2M38.2 151.4h1v1.6h-1zM38.4 158.7v.3M39.7 151.4h.9M40 154.8h.7l.3 .3v1.1l-.3 .2h-.7M40.1 151.4v1.6M40.2 157.4l.7 1.6 .8-1.6M40.2 154.8v1.6M41.1 152.2h.4M41.5 156.4h.4M41.5 154.8h.4"/>
<path d="M41.7 160h.9v1.6h-.9zM41.7 154.8v1.6M42 151.4h-.9v1.6h.9M42.1 157.4h.5M42.1 159h.5M42.4 157.4v1.6M43.1 160v1.6h.9M43.1 158.2h.4M43.3 155.1l-.2-.3h-.5l-.2 .3 .9 1.1-.2 .2h-.5l-.2-.2M43.4 151.7l-.2-.3h-.5l-.2 .3 .9 1-.2 .3h-.5l-.2-.3M43.8 155.6h.7l.3-.2v-.3l-.3-.3h-.7v1.6M43.9 152v.2"/>
<path d="M43.9 152.5v.2M44 157.4h-.9v1.6h.9M44.5 157.4l.5 1.6 .2-.8 .2 .8 .5-1.6M45.2 154.8v1.6h1M46.4 157.4h.4M46.4 159h.4M46.6 157.4v1.6M46.6 156.4v-.5l.5-1.1 .5 1.1v.5M46.6 155.9h1M47.3 160h.5M47.5 160v1.6M48.1 154.8l.4 .8v.8"/>
<path d="M48.3 160h.9l-.9 1.6h.9M48.3 157.4v1.6l-1-1.6v1.6M49 154.8l-.5 .8M49.7 157.4h-.7l-.3 .3v1l.3 .3h.7v-.8h-.3M50.6 160h-.9v1.6h.9M50.9 154.8h.9M51.4 154.8v1.6M51.6 157.4h.7l.2 .3v1l-.2 .3h-.7M51.8 157.4v1.6M52.3 154.8l.5 .8v.8M53 157.4h.5M53 159h.5"/>
<path d="M53.2 157.4v1.6M53.2 154.8l-.4 .8M53.7 155.6h.7l.2-.2v-.3l-.2-.3h-.7v1.6M53.9 158.2h.7l.3-.3v-.2l-.3-.3h-.7v1.6M54.2 158.2l.7 .8M55.1 155.6h.5M55.3 160h1v1.6h-1zM55.3 158.2h.5M56.1 154.8h-1v1.6h1M56.3 157.4h-1v1.6h1M56.5 155.4v.2M56.5 155.9v.3"/>
<path d="M56.8 160h.7l.2 .3v1l-.2 .3h-.7M57 160v1.6M57.7 157.7l-.2-.3h-.5l-.2 .3v1l.2 .3h.5l.2-.3M58.2 157.4h.9M58.6 157.4v1.6M59.1 160h-.9v1.6h.9M59.6 157.4h.5M59.6 159h.5M59.8 157.4v1.6M60.5 157.4h1v1.6h-1zM61.2 155.1l.3-.3v1.6M61.2 156.4h.5"/>
<path d="M62.2 156.2v.2M62.7 155.1l.2-.3h.5l.2 .3v.3l-.2 .2h-.3M62.9 157.4v1.6l-1-1.6v1.6M62.9 160h.9M63.4 157.9v.3M63.4 158.5v.2M63.4 160v1.6M63.4 155.6l.2 .3v.3l-.2 .2h-.5l-.2-.2M64.3 154.8l-.2 .6M64.6 154.8l-.3 .6M65.2 159v-.5l.5-1.1 .5 1.1v.5M65.2 158.5h1"/>
<path d="M66.5 154.8h.9M66.7 157.4v1.3l.2 .3M66.9 154.8v1.6M67.4 157.4v1.3l.2 .3M67.9 155.6h.5M68.1 160v1.6l-1-1.6v1.6M68.8 154.8h-.9v1.6M69.3 154.8h.9M69.8 154.8v1.6M71.4 160h.5M71.6 160v1.6M75.2 160h.4"/>
<path d="M75.4 160v1.6M76.1 160l.7 1.6 .7-1.6M78.9 160h-.9v1.6h.9M80.4 160l-1 1.6M81.8 160v1.6l-1-1.6v1.6M82.2 160h1v1.6h-1zM87.9 160v1.6h.9M89.3 160v1.6h1M90.7 160l.5 .8v.8M91.7 160l-.5 .8M93.6 160h.7l.2 .3v.2l-.2 .3M93.8 160v1.6"/>
<path d="M95 160v1.6h.9M99.2 160v1.6M100.1 160l-.6 .8h-.3M116.5 143.8v1.4h.9M117.8 144.5h.4M118.6 143.8h-.8v1.4h.8M119 143.8h.6l.3 .2v1l-.3 .2h-.6M119.2 143.8v1.4M120.3 145.2v-.5l.4-.9 .4 .9v.5M120.3 144.7h.8M121.2 152.8v1.5h.8M122.1 144.4h.1l.2 .3-.2 .1z"/>
<path d="M122.2 144l.4-.2v.2l-.2 .1zM122.2 144l.2 .1-.2 .3h-.1zM122.2 153.5h.6M122.4 144.7l.2 .1v.2l-.4-.2zM122.6 143.8l.3 .2-.1 .1-.2-.1zM122.6 144.8l.2-.1 .1 .1-.3 .2zM122.9 144.4h.2l-.2 .4-.1-.1zM122.9 144l.2 .4h-.2l-.1-.3zM123 144.4h4.7M123.1 152.8h-.9v1.5h.9M123.5 152.8h.3a.83 .83 0 0 1 .5 .7 .83 .83 0 0 1-.4 .8h-.4zM126.8 153.1a.43 .43 0 0 0-.6-.3 .97 .97 0 0 0 .1 1.5 .46 .46 0 0 0 .5-.4"/>
<path d="M127.2 152.8v1.5M127.7 153.5a.57 .57 0 0 0 .9-.4l-.3-.3h-.6v1.5M128.2 153.5l.4 .8M128.7 141.1h-1v5.9h4.7M129 141.1h.2M129.4 141.1h1.3M129.9 153.1l-.1-.2-.3-.1a.83 .83 0 0 0-.5 .7 .83 .83 0 0 0 .5 .8l.2-.1 .2-.3M130.3 152.8v1a.42 .42 0 0 0 .5 .5 .42 .42 0 0 0 .4-.5v-1M130.9 141.1h.2M131.4 141.1h1M131.7 152.8v1.5M132.2 152.8h.8"/>
<path d="M132.4 141v.3M132.4 141.6v.6l.6-.3M132.4 146.9v.3M132.4 147.4v.7l.6-.3M132.6 152.8v1.5M133 140.4l-.6-.4v.7M133 146.2l-.6-.3v.7M133.2 140.5l.2 .1M133.2 146.4l.2 .1M133.4 141.6l-.2 .1M133.4 147.5l-.2 .1M133.5 145l.4-.3-.2 .4z"/>
<path d="M133.6 145.1l-.7 .8M133.6 140.8l.6 .3M133.6 146.7l.6 .3M134.2 140v.7M134.2 141v.3M134.2 141.6v.6M134.2 145.9v.7M134.2 146.9v.3M134.2 147.4v.7M134.2 141.1l-.6 .4M134.2 141.1h1.1M134.2 147l-.6 .3"/>
<path d="M134.4 145l.4-.3-.3 .4zM134.4 145.1l-.7 .8M134.5 152.8h.3a.82 .82 0 0 1 .5 .7 .82 .82 0 0 1-.4 .8h-.4zM135.5 141.1h.3M135.8 152.8v1.5M136 141.1h1.3M136.3 154.3l.5-1.5 .5 1.5M136.4 153.8h.7M137.5 141.1h.2M138 141.1h1.1v5.9h-4.9M138.6 153.1a.49 .49 0 0 0-.6-.3 .49 .49 0 0 0-.4 .6l.2 .7 .2 .2 .3-.1 .2-.2 .1-.3h-.4M138.9 153.5a.57 .57 0 0 0 .9-.4l-.3-.3h-.6v1.5"/>
<path d="M139.1 144.4h4.9M139.3 153.5l.5 .8M140.2 154.3l.5-1.5 .5 1.5M140.4 153.8h.6M141.6 154.3v-1.5l.5 1.5 .5-1.5v1.5M143.1 154.2h.1zM143.2 153.3v.1zM143.9 144.4h.2l.1 .3-.1 .1zM144.1 144l.3-.2v.2l-.2 .1zM144.1 144l.1 .1-.1 .3h-.2zM144.2 144.7l.2 .1v.2l-.3-.2zM144.4 143.8l.4 .2-.1 .1-.3-.1z"/>
<path d="M144.4 144.8l.3-.1 .1 .1-.4 .2zM144.8 144l.1 .4h-.1l-.1-.3zM144.8 144.4h.1l-.1 .4-.1-.1zM145.4 143.6v1.4h.8M146.6 144.3h.5M147.5 143.6h-.9v1.4h.9M147.9 143.6h.6l.2 .2v.9l-.2 .3h-.6M148.1 143.6v1.4M149.1 143.6v1.4M149.4 144.3l.6 .7M150 143.6l-.6 .7h-.3M37 160.3l.2-.3h.4l.3 .3v.2l-.3 .3h-.2"/>
<path d="M37 171.5h1l-.7 1.6M37.2 175.2l-.2-.3v-.3l.2-.2h.5l.3 .2v.3l-.3 .3h-.5l-.2 .3v.2l.2 .3h.5l.3-.3v-.2l-.3-.3M37.6 160.8l.3 .2v.3l-.3 .3h-.4l-.2-.3M37.9 178.3h-.7l-.2-.3v-.3l.2-.3h.4l.3 .3v.8l-.5 .5h-.2M38 168.8h-.3l-.5 .5v.8l.3 .3h.5l.2-.3v-.2l-.2-.3h-.8M38 163.8h-1l.6-1.1v1.6M38.1 165.6h-1v.6h.8l.2 .2v.5l-.2 .3h-.5l-.3-.3M38.4 164.1v.2v-.1M38.4 161.3v.3M38.4 178.8v.2M38.4 172.8v.3M38.4 175.7v.3"/>
<path d="M38.6 166.9v.3M38.7 170.1v.3M40.2 162.7h.5a.77 .77 0 0 1 .4 1.2l-.4 .4h-.5zM40.2 177.4v1.4l.3 .2h.4l.3-.2v-1.4M40.2 160.8h.7l.3-.3v-.2l-.3-.3h-.7v1.6M40.3 171.5h.7l.3 .3v.2l-.3 .3M40.3 174.4v1.6h1M40.4 165.6h1v1.6h-1zM40.6 172.3h.4l.3 .3v.2l-.3 .3h-.7M40.6 171.5v1.6M41.5 169.1l-.2-.3h-.5l-.3 .3 1 1-.2 .3h-.5l-.3-.3M41.7 163.5h.6l.2-.2 .1-.4-.3-.2h-.6v1.6"/>
<path d="M41.7 173.1v-.5l.5-1.1 .5 1.1v.5M41.7 172.6h1M41.9 166.4h.7l.2-.2v-.3l-.2-.3h-.7v1.6M42 168.8h.9M42.1 163.5l.5 .8M42.4 168.8v1.6M42.6 177.4v1.6l-.9-1.6v1.6M42.7 174.6l-.3-.2h-.4l-.3 .2v1.1l.3 .3h.4l.3-.3M43.1 179v-1.6l.4 1.1 .5-1.1v1.6M43.1 162.7v1.6M43.1 176v-1.6l.5 1.1 .5-1.1v1.6M43.3 166.4h.4"/>
<path d="M43.4 168.8h.9v1.6h-.9zM43.6 162.7l.6 1.6 .5-1.6M44.1 171.8l-.2-.3h-.5l-.3 .3v1l.3 .3h.5l.2-.3M44.2 165.6h-.9v1.6h.9M44.5 179v-.5l.5-1.1 .4 1.1v.5M44.5 161.6v-.6l.5-1 .4 1v.6M44.5 178.5h.9M44.5 161h.9M44.6 171.5v1.6M44.7 166.4h.7l.3-.2v-.3l-.3-.3h-.7v1.6M44.8 169.6h.7l.2-.3v-.2l-.2-.3h-.7v1.6M44.8 172.3l.7 .8"/>
<path d="M44.9 166.4l.8 .8M45 163.5h.5M45 169.6l.7 .8M45.5 171.5l-.7 .8h-.2M45.9 162.7h-.9v1.6h.9M45.9 178.3h.7l.2-.3v-.3l-.2-.3h-.7v1.6M45.9 160.8h.7l.2-.3v-.2l-.2-.3h-.7v1.6M46 174.4v1.6h.9M46.1 167.2v-.5l.5-1.1 .5 1.1v.5M46.1 160.8l.7 .8M46.1 166.7h1M46.2 178.3l.6 .7"/>
<path d="M46.2 170.4v-.5l.5-1.1 .5 1.1v.5M46.2 169.9h1M46.3 163.5h.6l.2-.2v-.4l-.3-.2h-.5v1.6M46.7 163.5l.5 .8M47.3 177.4v1.6M47.3 161.6h.5M47.4 171.5v1.6h.9M47.4 174.9v.8l.2 .3h.3l.4-.5M47.5 165.6h1M47.6 178.3l.7 .7M48 165.6v1.6M48.3 177.4l-.7 .9h-.3"/>
<path d="M48.3 174.9v1.1M48.6 168.8h-.7l-.3 .3v1l.3 .3h.7v-.8h-.3M48.7 178.3h.5M48.8 175.2l.2-.3 .3 .3v.3M48.8 171.5h.5M48.8 173.1h.5M48.8 174.9v1.1M49 167.2h.4M49 165.6h.4M49 162.7v1.6M49.1 169.6h.4M49.1 171.5v1.6"/>
<path d="M49.2 165.6v1.6M49.3 175.2l.2-.3 .2 .3v.8M49.7 177.4h-1v1.6h1M49.7 160.8h.5M50 168.8h-.9v1.6h.9M50.2 177.4h.7l.2 .3v1.1l-.2 .2h-.7M50.2 174.4v.2M50.2 174.9v1.1M50.4 177.4v1.6M50.5 163.1l-.1-.3-.3-.1a.86 .86 0 0 0-.6 .7 .86 .86 0 0 0 .3 .8l.1 .1a.5 .5 0 0 0 .6-.4M50.7 171.5h-.7l-.3 .3v1l.3 .3h.7v-.8h-.2M50.7 175.5l.5-.6h.2l.2 .3v.8"/>
<path d="M50.7 174.9v1.1M50.8 165.6v1.6l-.9-1.6v1.6M50.9 163.3h.1v.1zM51 164.1v.2zM51.1 160.8h.7l.2-.3v-.2l-.2-.3h-.7v1.6M51.2 171.5v1.6M51.2 172.3h.9M51.4 160.8l.6 .8M51.9 168.8h.9M52.1 175.2l.2-.3h.3l.2 .3v.5l-.2 .3h-.3l-.2-.3zM52.1 171.5v1.6M52.3 165.6h-.8l-.2 .3v1l.2 .3h.8v-.8h-.3"/>
<path d="M52.4 168.8v1.6M52.6 171.5h.9M52.8 175.7l.3 .3M52.9 162.9a.53 .53 0 0 0-.6-.2 .53 .53 0 0 0-.4 .4 .53 .53 0 0 0 .6 .4l.3 .3 .1 .3a.55 .55 0 0 1-1 0M53 177.4h.9M53.1 171.5v1.6M53.3 162.7h.9M53.3 169.6h.5M53.5 177.4v1.6M53.5 175.5l.5-.6h.2l.3 .3v.8M53.5 174.9v1.1M53.7 162.7v1.6"/>
<path d="M53.9 161.6v-1.6l.5 1 .5-1v1.6M54 172v.3M54 172.6v.2M54.2 165.6h.9M54.2 168.8h-.9v1.6h.9M54.4 177.4h.9v1.6h-.9zM54.5 162.7h.9l-.7 1.6M54.6 165.6v1.6M54.7 170.4v-1.6l.5 1.1 .5-1.1v1.6M55.6 166.4h.4M55.8 177.4v1.6h1M55.8 162.7h1l-.7 1.6"/>
<path d="M55.9 174.9h-.7l-.3 .3v.5l.3 .3h.7M55.9 171.8l.2-.3h.5l.2 .3v.2l-.2 .3h-.5l-.2 .3v.5h.9M56.1 169.6h.7l.3-.3v-.2l-.3-.3h-.7v1.6M56.4 175.5h.7l.2-.3-.2-.3h-.5l-.2 .3v.5l.2 .3h.5M56.5 165.6h-.9v1.6h.9M57 167.2v-1.6l.5 1.1 .4-1.1v1.6M57.2 178.3h.5M57.3 162.8a.35 .35 0 0 0 .2 .5 .55 .55 0 0 1 .5 .3 .55 .55 0 0 1 0 .6l-.5 .1-.3-.2v-.3l.1-.2 .6-.3a.35 .35 0 0 0 .1-.5zM57.5 170.1v.3M57.7 174.9v.3M57.7 175.5v.2M58 169.3v.3"/>
<path d="M58 169.9v.2M58.2 177.4h-1v1.6h1M58.2 160.8h.4M58.3 171.8l-.3-.3h-.5l-.2 .3v1l.2 .3h.5l.3-.3M58.4 166.4h.7l.2-.2v-.3l-.2-.3h-.7v1.6M58.6 178.3h.8l.2-.3v-.3l-.2-.3h-.8v1.6M58.7 172.3h1M58.7 171.5v1.6M58.9 178.3l.7 .7M59.4 163.3a.47 .47 0 0 1-.5 .4 .47 .47 0 0 1-.4-.5 .47 .47 0 0 1 .4-.5 .63 .63 0 0 1 .5 .9l-.2 .6-.3 .1-.3-.2M59.6 160.5v.3M59.6 161v.3"/>
<path d="M59.7 174.6l.2-.2h.5l.2 .2v.3l-.2 .3h-.5l-.2 .3v.5h.9M59.7 171.5v1.6M59.8 166.9v.3M59.9 162.7l.5 1.6 .6-1.6M60.1 179v-.5l.4-1.1 .5 1.1v.5M60.1 178.5h.9M60.1 171.5h.5M60.1 173.1h.5M60.3 166.2v.2M60.3 166.7v.2M60.4 171.5v1.6M61.1 172.3h.7l.2-.3v-.2l-.2-.3h-.7v1.6"/>
<path d="M62 174.4h-.9v.5h.7l.2 .3v.5l-.2 .3h-.5l-.2-.3M62.4 177.4v1.6l-.9-1.6v1.6M62.5 174.6l.2-.2h.2l.3 .2v1.1l-.3 .3h-.2l-.2-.3zM62.5 172.3h.9M62.7 169.6h1M63.9 177.7l-.3-.3h-.5l-.2 .3v1.1l.2 .2h.5l.3-.2M63.9 171.5l.5 1.6 .2-.8 .3 .8 .4-1.6M64.1 169.1l.3-.3h.5l.2 .3v.2l-.2 .3h-.3M64.3 160.8h.7l.2-.3v-.2l-.2-.3h-.7v1.6M64.3 178.3h.5M64.5 160.8l.7 .8M64.9 169.6l.2 .3v.2l-.2 .3h-.5l-.3-.3"/>
<path d="M65 166.4h.9M65.3 177.4h-1v1.6h1M65.7 161.6v-.6l.5-1 .5 1v.6M65.7 161h1M65.8 178v.3M65.8 178.5v.3M65.8 168.8h.2l.3 .3v1l-.3 .3h-.2l-.2-.3v-1zM65.8 172.3h.9M65.8 171.5v1.6M66 174.6l-.2-.2h-.5l-.2 .2v1.1l.2 .3h.5l.2-.3M66.2 178.8h.9M66.2 178h.9"/>
<path d="M66.4 165.9l.3-.3h.4l.2 .3v.3l-.2 .2h-.4l-.3 .3v.5h.9M66.5 174.4h.7l.2 .2v1.1l-.2 .3h-.7M66.7 177.4v1.1M66.7 174.4v1.6M66.7 171.5v1.6M67 168.8l.2 .3-.2 .3-.3-.3zM67.2 171.5h.5M67.2 173.1h.5M67.4 171.5v1.6M67.8 177.4h.3l.2 .3v1.1l-.2 .2h-.3l-.2-.2v-1.1zM68.1 165.6h.2l.2 .3v1l-.2 .3h-.2l-.3-.3v-1zM68.2 171.5h.9"/>
<path d="M68.6 169.1l-.2-.3h-.5l-.2 .3v1l.2 .3h.5l.2-.3M68.6 171.5v1.6M68.8 178.8v.2M68.9 174.4l-1 1.6M69.2 165.6l.3 .3-.3 .3-.2-.3zM69.3 177.7l.2-.3h.5l.2 .3v.3l-.2 .3h-.5l-.2 .2v.5h.9M69.3 176v-1.6l.5 1.1 .5-1.1v1.6M69.5 160.3l-.2-.3h-.5l-.3 .3 1 1-.2 .3h-.5l-.3-.3M69.6 172.3h.4M70 161.6v-1.6l.4 1 .5-1v1.6M70 169.3l-.2 .3-.5-.3-.2 .3M70.5 171.5h-.9v1.6h.9"/>
<path d="M70.7 169.6l-.2-.3v-.2l.2-.3h.5l.3 .3v.2l-.3 .3h-.5l-.2 .3v.2l.2 .3h.5l.3-.3v-.2l-.3-.3M70.7 174.6l.3-.2h.4l.3 .2v.3l-.3 .3h-.4l-.3 .3v.5h1M70.9 165.9l-.3-.3h-.4l-.2 .3v1l.2 .3h.4l.3-.3M71.4 161.6h.5M72.1 168.8h.3l.2 .3v1l-.2 .3h-.3l-.2-.3v-1zM72.3 166.2l-.2 .2-.5-.2-.2 .2M72.4 171.5v1.6h.9M72.6 174.4l-.4 .5v.6l.4 .5M72.8 165.6h.9l-.7 1.6M73.1 174.4h.9M73.3 160.3l-.3-.3h-.4l-.3 .3 1 1-.3 .3h-.4l-.3-.3M73.3 168.8l.3 .3-.3 .3-.2-.3z"/>
<path d="M73.6 174.4v1.6M73.8 172.3h.5M74.4 165.6h.3l.2 .3v1l-.2 .3h-.3l-.2-.3v-1zM74.5 174.4l.5 .8v.8M74.7 160.3l-.2-.3h-.5l-.2 .3 .9 1-.2 .3h-.5l-.2-.3M74.8 171.5h-1v1.6h1M75 169.1l-.2-.3h-.5l-.3 .3v1l.3 .3h.5l.2-.3M75.2 161.6h.4M75.2 171.5h.8l.2 .3v1l-.2 .3h-.8M75.4 165.9l.2-.3 .2 .3-.2 .3zM75.4 174.4l-.4 .8M75.5 171.5v1.6"/>
<path d="M75.9 175.2h.8l.2-.3v-.3l-.2-.2h-.8v1.6M76.9 172.6v.5l-.2 .3M76.9 172v.3M77.2 165.9l-.2-.3h-.5l-.2 .3v1l.2 .3h.5l.2-.3M77.3 174.4l.5 .5v.6l-.5 .5M78 160.8h.5M79.7 172.6h-.9l.7-1.1v1.6M80.4 171.5h.3l.2 .3v1l-.2 .3h-.3l-.2-.3v-1zM81.4 173.1v-1.6l.4 1.1 .5-1.1v1.6M82.8 173.1v-.5l.5-1.1 .4 1.1v.5M82.8 172.6h.9M83.7 160.8h.7l.2-.3v-.2l-.2-.3h-.7v1.6"/>
<path d="M83.9 160.8l.7 .8M84.4 172.8v.3l-.2 .3M84.9 171.8l.2-.3h.5l.3 .3v.2l-.3 .3h-.2M85.1 161.6v-1.6l.4 1 .5-1v1.6M85.6 172.3l.3 .3v.2l-.3 .3h-.5l-.2-.3M86.3 172.8v.3M86.5 161.6v-.6l.5-1 .4 1v.6M86.5 161h.9M87 171.5h.3l.2 .3v1l-.2 .3h-.3l-.2-.3v-1zM88 171.5l.7 1.6 .7-1.6M93.8 160.8h.5l.2 .2v.3l-.2 .3h-.7M96.4 161.6v-.6l.5-1 .4 1v.6"/>
<path d="M96.4 161h.9M98.7 160.3l-.2-.3h-.4l-.3 .3v1l.3 .3h.4l.2-.3M99.5 160.8l.6 .8M122.7 170.6h133.3M145.6 164.3v25.6M145.6 177.1h19M145.6 173.9h19M157 173.9v6.4M158.5 178.7h1M159.4 178.4l.3-.1 .2 .1 .1 .3-.1 .3-.2 .1-.3-.1-.1-.3zM159.7 177.4v.9M159.7 178.5v.3"/>
<path d="M159.7 179.1v.9M159.7 178.7h.3M160.2 178.7h1.2M160.8 178.3l1.9-.5v1.7l-1.9-.4zM161.7 178.7h.2M162.2 178.7h.9M164.6 170.6v19.3M167 165.7v2.7h1.3M169 165.7l.1 .1-.1 .1-.1-.1zM169 166.5v1.9M169.8 167.1l.6-.6h.3l.2 .2 .2 .4v1.3M169.8 166.5v1.9"/>
<path d="M171.1 167.1l.5-.6h.4l.2 .2 .1 .4v1.3M172.3 170.6v19.3M173.3 165.7l.1 .1-.1 .1-.1-.1zM173.3 166.5v1.9M174.1 166.5h.8M174.5 165.7v2.1l.1 .4 .4 .2M175.8 166.9a.74 .74 0 0 1 .9-.4 .74 .74 0 0 1 .5 .8 .78 .78 0 0 1-.4 .9 .78 .78 0 0 1-1-.2l-.1-.4zM180 166.5h.8M180.4 165.7v2.1l.1 .4 .4 .2M181.6 167.3h1.4a.66 .66 0 0 0-.5-.7 .66 .66 0 0 0-.8 .3 .91 .91 0 0 0 .8 1.5l.5-.4M185 166.9l-.3-.3-.4-.1a.96 .96 0 0 0-.7 1 .96 .96 0 0 0 .7 .9l.4-.1 .3-.3M185.7 167.1l.5-.6h.4l.2 .2 .1 .4v1.3"/>
<path d="M185.7 165.7v2.7M187.8 167.1l.6-.6h.4l.2 .2 .1 1.7M187.8 166.5v1.9M190.3 166.7a.78 .78 0 0 1 .9 0 .78 .78 0 0 1 .3 .9 .74 .74 0 0 1-.8 .8 .74 .74 0 0 1-.7-.8l.1-.7zM192.1 165.7v2.7M193.4 166.7a.77 .77 0 0 1 .9 0 .77 .77 0 0 1 .2 .9 .76 .76 0 0 1-.9 .8 .76 .76 0 0 1-.5-1.1l.1-.4zM196.6 166.5v2.1l-.1 .4a.63 .63 0 0 1-1 .1M196.6 166.9a.76 .76 0 0 0-1-.3 .76 .76 0 0 0-.4 1 .72 .72 0 0 0 .5 .8 .72 .72 0 0 0 .9-.4M197.4 166.5l.7 1.9 .7-1.9M198.1 168.4l-.4 .8h-.3M201.3 165.7v2.7M202.2 167.1l.6-.6h.3l.3 .2 .1 .4v1.3"/>
<path d="M202.2 166.5v1.9M205.7 166.9l-.3-.3-.3-.1a.96 .96 0 0 0-.7 1 .96 .96 0 0 0 .7 .9l.3-.1 .3-.3M206.6 168.1l-.2 .1 .2 .2 .1-.2M233.2 173.9h22.8M233.2 167.4h22.8M233.2 164.3v25.6M235.1 178.1a.43 .43 0 0 0-.4-.2 .43 .43 0 0 0-.3 .3l.1 .2 .5 .2 .2 .2-.1 .2-.1 .2h-.3l-.3-.2M237.2 178.5a.38 .38 0 0 0-.6 0 .38 .38 0 0 0 0 .5 .38 .38 0 0 0 .6 0M237.2 177.9v1.3M238.2 178.5l-.3-.2a.48 .48 0 0 0-.2 .8l.2 .1 .3-.2M238.2 168.7l.2-.2v1.1M238.2 178.3v.9"/>
<path d="M238.9 169.5v.1l.1-.1M239.4 168.5h.6l-.3 .4h.1a.35 .35 0 0 1 .1 .6 .35 .35 0 0 1-.5-.1M239.6 177.9v1.3h.7M240.4 168.4h-.1h.1l-.1 .2M240.6 177.9v.1zM240.6 178.3v.9M240.8 168.4h-.1h.1l-.1 .2M241 178.6l.2-.3h.2l.2 .3v.6M241 178.3v.9M241.6 178.6l.2-.3 .3 .1 .1 .8M242.6 178.7h.7v-.1a.34 .34 0 0 0-.5-.2 .34 .34 0 0 0-.2 .4 .34 .34 0 0 0 .3 .4 .34 .34 0 0 0 .4-.2M245.6 177.7l-1 1.9"/>
<path d="M246.9 178.6l.6-.1 .1-.2-.1-.3-.6-.1v1.3M248.4 164.3v6.3M249 177.9v1.3M249.5 178.3l.4 .9 .3-.9M249.9 179.2l-.2 .4h-.2M250.4 177.9v.1zM250.4 178.3v.9M250.8 178.6l.3-.3h.1l.2 .2v.7M250.8 178.3v.9M251.4 178.6l.3-.3h.2l.1 .2v.7M252.5 177.9v.1zM252.5 178.3v.9"/>
<path d="M253.5 178.5l-.3-.2a.48 .48 0 0 0-.2 .8l.2 .1 .3-.2M253.5 177.9v1.3M253.9 178.7h.6a.33 .33 0 0 0-.3-.4 .33 .33 0 0 0-.3 .4v.1a.35 .35 0 0 0 .2 .4 .35 .35 0 0 0 .4-.2M256 164.3h-133.3v25.6M36.6 180.3l.2-.3v1.6M36.6 181.6h.5M36.9 182.9l.3-.3v1.6M37.8 180h.2l.2 .3v1l-.2 .3h-.2l-.2-.3v-1zM38 182.9l.3-.3v1.6M38.7 181.3v.3M39.1 184l-.1 .1h.1M40.8 181.1l.6 .6h.2"/>
<path d="M41 180.3l-.2 .1M41 180.3l-.1 .5M41 180.7l-.3 1M41 180.8h-.2M41.2 183.3v.7l-.1 .3M41.3 180.1v1.3M41.4 183.1l.1 .2M41.5 182.6v.3M41.5 180.3h-.4M41.5 180.7l-.4 .1M41.5 180.9l-.4 .1M41.5 180.2l-.1 .5"/>
<path d="M41.5 181.1l-.4 .1M41.6 180.5l-.6 .1M41.7 183l-.1 .4M41.9 182.9l-.7 .1M41.9 180.2l.1 .3M41.9 183.3l-.7 .1M42 180.7v.7M42 180.7l-.3 .1M42.1 180.5l.3 1h.2M42.1 181.2l-.2 .3M42.2 183.5v.6M42.2 180.1l.1 .4"/>
<path d="M42.2 183.6h.2v.4M42.4 180.2l-.1 .7-.3 .8M42.4 182.8v.6M42.4 184h-.2M42.6 183.5v.6M42.6 183.6h.3l-.1 .4M42.7 182.8v.5h-.3M42.7 182.9h-.3M42.9 184h-.3M43 180.7l-.3 .6M43 180.8l.1 .2M43 180.1v1.6"/>
<path d="M43.2 180.6l-.4 .1M43.2 180.3l-.1 1.4M43.3 183.4v.8M43.4 182.9l-.1 .6-.2 .2M43.4 180.3l.1 1.2h.1v-.2M43.4 182.7l-.2 .5M43.4 180.3l-.2 .1M43.5 183.6l.1 .2M43.6 182.9h-.3M43.7 182.6l-.2 .6M43.7 182.9l.1 .2M43.8 183.2v1l-.2-.2"/>
<path d="M43.9 180.7l-.1 .4M43.9 182.9h-.3M44 183.4l-.5 .1M44.1 181l-.1 .6-.2 .1M44.2 180.1v.5M44.3 181v.5l.1 .2h.2v-.4M44.3 181.1h-.2M44.4 183.7v.5M44.4 180.6l-.4 .1M44.5 182.9l.4 .7h.1M44.5 180.3l-.6 .2M44.5 180.8l-.6 .1"/>
<path d="M44.6 180.7l-.2 .4M44.6 182.7l-.4 .9M44.8 183.4l-.5 .1M44.8 183.7v.4l-.4 .1M44.8 183.7h-.4M45.1 183.3h.6l.3-.1v-.5l-.3-.1h-.6v1.6M45.2 180.2l-.1 1.1-.2 .3M45.4 180.2v1.5M45.6 183.3l.4 .9M45.6 180.2l-.7 .1M45.7 180.7l-.9 .1M46 180.3l-.1 .4"/>
<path d="M46 180.9v.8M46.2 181.2l.1 .2M46.2 180.1l.1 .2M46.2 180.5l-.3 .4M46.3 180.6l-.1 .3M46.3 180.9l-.3 .5M46.3 180.5l.3 .3M46.4 181.1h-.2M46.5 181l-.4 .6M46.5 181.5l-.5 .1M46.5 180.8v.9M46.5 180.8l-.5 .2"/>
<path d="M46.7 180.3l-.8 .2M46.7 180.3l-.1 .3M46.8 182.6h.4a.96 .96 0 0 1 0 1.6h-.3a.99 .99 0 0 1-.1-1.6zM47.1 180.7l.3-.1v.5M47.1 180.6v.6M47.4 181.1h-.3M47.5 180.3v1.4l-.2-.4M47.7 180.2l-.9 .2M48 182.6v1.6M48 183.3h.9M48 180.2l.1 .2M48.1 180.8l.1 .2"/>
<path d="M48.1 180.7l-.2 .4M48.1 180.6h-.2M48.2 180.5l-.1 1.2M48.4 180.2v.8M48.5 180.5a1.22 1.22 0 0 1-.4 1.2M48.5 181v.5h.3v-.3M48.7 180.2l-.1 .9M48.7 180.3h-.3M48.9 182.6v1.6M49 180.2v1.4M49.2 180.6l.4 .7M49.6 180.5l-.5 .9"/>
<path d="M49.7 180.3l-.7 .1M49.7 181.5l-.7 .1M50.1 180.3v1.2M50.3 181.3l-.3 .3M50.3 180.8l-.2 .1M50.4 180.2v1.3l.4 .1v-.4M50.4 182.8a.52 .52 0 0 0-.5-.2 .52 .52 0 0 0-.4 .3l.2 .4a.78 .78 0 0 1 .7 .4v.2a.56 .56 0 0 1-.9 0M50.7 180.6l-.3 .5M51.1 182.7v1.5M51.2 183.5l-.1-.3-.2 .5M51.2 183.1l-.3 .1M51.4 184l.1 .2"/>
<path d="M51.4 183.5l-.2 .5M51.5 183.3v.9M51.6 183.5l.2 .4M51.7 182.8l-.4 .1M51.8 183.2l-.5 .1M52 183l.1 .2M52.2 183.2l-.2 .8v-.2M52.3 180v1.6h1M52.5 182.7l-.3 .7M52.5 182.8l.1 .2M52.6 183.2l-.1 .9M52.7 183.7l-.3 .1"/>
<path d="M52.7 183.1l-.4 .1v1M52.7 183.4l-.3 .1M52.8 184.1h-.5M54.7 180.3l-.2-.3h-.5l-.3 .3v1l.3 .3h.5l.2-.3M55.1 180h.8l.2 .3v1l-.2 .3h-.8M55.4 180v1.6M58 181.6v-.5l.4-1.1 .5 1.1v.5M58 181.1h.9M59.4 181.3v.3M59.9 181.6v-.5l.4-1.1 .5 1.1v.5M59.9 181.1h.9M61.5 180.2v1.4"/>
<path d="M61.6 180.6l.4 .7M62 180.5l-.5 .9M62.2 180.3l-.7 .1M62.2 181.5l-.8 .1M62.6 180.5v.6M62.6 180.6l.5-.1v.5M62.7 180.1l.1 .4M62.9 180.5v1.2M63 180.1l-.1 .4M63 180.7l-.3 .1M63.1 181h-.5M63.3 181.2h-.9"/>
<path d="M63.4 181.4l.8 .3 .1-.1M63.5 180.3l.2 .2M63.7 180.7l-.1 .7M63.7 180.8l-.3 .1M64 180.1l-.2 1.3M64.2 180.6l-.4 .1M64.2 180.5l-.1 .9-.1-.2M64.9 180.7l.2 .9h.2M64.9 180.7l-.2 .7-.2 .3M64.9 180.1v.6M65.3 180.7l-.8 .1M67.1 180h.2l.2 .3v1l-.2 .3h-.2l-.2-.3v-1z"/>
<path d="M68 181.3v.3M69.4 180h-.9v.6h.7l.2 .2v.5l-.2 .3h-.5l-.2-.3M69.9 180.8l.2-.2 .3 .2v.3M69.9 180.6v1M70.4 180.8l.2-.2 .2 .2v.8M71.3 180.8l.3-.2 .2 .2v.3M71.3 180.6v1M71.8 180.8l.2-.2 .2 .2v.8M145.6 186.7h110.4M145.6 183.5h110.4M145.6 180.3h87.6M157 183.5v6.4"/>
<path d="M158.8 185h1.2M158.8 185.8h1.2M159.4 184.3v1.4M159.9 188.2h1.2M159.9 189.1h1.2M160.4 184.4l.4-.1a.99 .99 0 0 1 .3 1.3 .41 .41 0 0 1-.4 .3 .41 .41 0 0 1-.4-.3 1.4 1.4 0 0 1 .1-1.2zM160.5 187.5v1.4M161.3 187.8l.3-.3v1.6M161.7 185.8h-.1h.1M162.4 184.3h.7l-.4 .6a.51 .51 0 0 1 .4 .8 .51 .51 0 0 1-.9-.1M175.3 187.9l.1-.2 .5-.2 .2 .2v.3l-.2 .5-.7 .6h1M176.8 187.6a.48 .48 0 0 1 .7 .2 1.61 1.61 0 0 1-.2 1.3 .49 .49 0 0 1-.7-.3 1.61 1.61 0 0 1 .2-1.2z"/>
<path d="M177.2 184.3v1.5l-.3 .1-.2-.1-.2-.4M177.6 185.3h.8a.41 .41 0 0 0-.4-.5 .41 .41 0 0 0-.4 .5 .46 .46 0 0 0 .6 .6l.2-.2M177.9 187.8l.4-.3v1.6M179 187.5h1l-.7 1.6M179.6 185.1a.4 .4 0 0 0-.4-.3 .4 .4 0 0 0-.4 .3 .69 .69 0 0 0 .7 .3l.1 .3a.44 .44 0 0 1-.8 0M180 185.3h.8l-.1-.4-.4-.1a.6 .6 0 0 0 0 1.1h.3l.2-.2M180.4 187.8l.3-.3v1.6M181.2 185.2l.4-.4 .3 .1 .1 1M181.2 184.8v1.1M181.6 187.9v-.2l.5-.2 .2 .2 .1 .3-.3 .5-.6 .6h.9M182.8 187.8l.4-.3v1.6M184 187.9l.1-.2 .5-.2 .2 .2v.3l-.2 .5-.7 .6h1"/>
<path d="M187.5 180.3v9.6M193.4 181.9h.6M194.3 181.1h-.9v1.6h.9M194.8 182.5v.2l.1-.1M195.4 181.9h.5M196.3 181.1h-.9v1.6h.9M196.8 182.5v.2v-.1M202.7 180.3v9.6M204.3 181.9h.7l.2-.1v-.4l-.1-.2-.8-.1v1.6M206.5 181.9a.5 .5 0 0 0-.8 0 .5 .5 0 0 0 .2 .7l.4 .1 .2-.2M206.5 181.6v1.1M207 181.9l.3-.3 .4 .1v1"/>
<path d="M207 181.6v1.1M208.3 182.1h.8a.4 .4 0 0 0-.4-.5 .4 .4 0 0 0-.4 .5 .44 .44 0 0 0 .2 .5 .44 .44 0 0 0 .6-.1M209.5 181.1v1.6M212.6 180.8l-1.2 2.5M214.2 181.9h.5M215 181.1h-.8v1.6h.8M215.5 182.5v.2l.1-.1M218 180.3v9.6M223.9 181.9h.7l.2-.1 .1-.4-.2-.2-.8-.1v1.6M225.4 182.5v.2l.1-.1M226 182.7v-1.6l.6 1.6 .5-1.6v1.6M227.7 182.5v.2l.1-.1"/>
<path d="M240.8 183.5v6.4M248.4 183.5v6.4"/>
<circle cx="159.7" cy="178.7" r=".81"/>
<circle cx="235.8" cy="178.7" r=".41"/>
<circle cx="248.4" cy="178.7" r=".41"/>
</g>
<g fill="#000">
<path d="M47.4 59h.4l-.2 1.5zM51.6 59h.4l-.2 1.5zM55.7 46.9l1.3-.2v.5zM56.1 54.3l1.2-.2v.4zM55.9 50.5l1.5-.2v.5zM57.1 57.9l1.3-.2v.5zM78.7 57.7l1.3 .2-1.3 .3zM78.7 55.9l1.3 .3-1.3 .2zM79.7 50.3l1.4 .2-1.4 .3zM79.7 54.1l1.3 .2-1.3 .2zM79.7 51.6l1.3 .2-1.3 .2zM80.1 46.7l1.2 .2-1.2 .3z"/>
<path d="M81.3 56.2l1.3-.3v.5zM81.3 51.8l1.3-.2v.4zM94.9 53.9l1.3 .2-1.3 .2zM97.7 54.1l1.3-.2v.4zM39.6 60.5l.2 1.4h-.5zM43.8 60.6l.2 1.7h-.5zM47.6 60.7l.2 1.4h-.4zM51.8 61.9l.2 1.5h-.4zM169.4 77.9l.2 1.6h-.4zM39.3 91.2h.5l-.2 1.4zM43.5 87.3h.5l-.2 1.7zM45.7 92.6l.2 1.1h-.4z"/>
<path d="M47.4 87.2h.4l-.2 1.4zM51.6 86.3h.4l-.2 1.4zM56 89v.9zM56 89h.2l-.2 .9zM56.2 89v.9h-.2zM56.2 89h.4l-.4 .3zM56.2 89.3l.4-.3v.3zM56.2 89.6h.4l-.4 .3zM56.2 89.9l.4-.3v.3zM56.8 89v.9zM56.6 89h.2l-.2 .9zM56.8 89v.9h-.2z"/>
<path d="M57.3 88.5l.2 .4-1.1 .6zM80 88.1l.7 1.1-1.1-.8zM80.3 89v.9zM80.3 89h.2l-.2 .9zM80.5 89v.9h-.2zM80.5 89h.3l-.3 .3zM80.5 89.3l.3-.3v.3zM80.5 89.6h.3l-.3 .3zM80.5 89.9l.3-.3v.3zM81.1 89v.9zM80.8 89h.3l-.3 .9zM81.1 89v.9h-.3z"/>
<path d="M95 89.2l1.3 .2-1.3 .3zM96.4 95.8l.2 .8h-.2zM96.4 95.8l.2 .1v.7zM97 92.6l.2 1.4h-.2zM97 94l-.4 1.9-.2-.1zM97 92.6h.2v1.4zM97 94h.2l-.6 1.9zM97.6 89.4l1.2-.2v.5zM103.3 99.7l.7-.1 .1 .1zM103.6 97l.5-.1 .1 .1zM104.6 97.5l.3-.1 .1 .1zM104.8 98.3l.2-.1-.2 .2z"/>
<path d="M105.2 99.5l.4-.1v.1zM105.2 97l.4-.1 .2 .1zM105.2 97.7h.6v.1zM106.2 100.1l.4-.1zM106.6 99.6l-.1 .1zM106.3 97.4h.3l.1-.1 .1 .1zM106.8 99.6l.5-.1v.1zM107.7 97.7l.1 .1zM108 97.9l.1 .1h-.1zM108.2 99.4h.4zM108.5 98.4l.2 .1zM108 97.3h.5l.1 .1z"/>
<path d="M108.5 97.6l.1 .1zM108.4 99.2l.3-.1 .1 .1zM109.3 99.1l.2-.1 .2 .1zM110.1 97.7h.1v.1zM109.4 97.1h.9v-.1l.2 .2zM110.8 100.1l.4-.1zM111.3 99.7h.5l.1-.2 .1 .2zM169.2 90.9h.4l-.2 1.7zM177.7 93.7l.7 1.1-.3 .3zM191.5 94.6l1-.9-.6 1.2zM204.9 93.1l.2 1.4h-.4zM204.7 91.1h.4l-.2 1.5z"/>
<path d="M45.5 107.9h.4l-.2 1.1zM55.8 104.3l1.5-.3v.6zM60 105.7l.1 1.1h-.3zM59.8 107.9h.3l-.1 1.1zM63.8 104l1.4 .3-1.4 .3zM65.8 113.7l.9 .2-.9 .2zM65.2 118.3l1-.2v.4zM65.8 116l.9-.2v.4zM67.1 111.1l.9 .1-.9 .2zM67.2 113.9l1-.2v.4zM68.3 111.2l1-.1v.3zM76 115.8l1 .2-1 .2z"/>
<path d="M76.5 118.1l1 .2-1 .2zM77.6 108.8l1.1-.2v.4zM95.5 112.5l.9 .2-.9 .2zM96.7 112.7l1-.2v.4zM108.3 100.5h.1zM109.3 100.5h.2zM112 100.2v.2h-.1zM123.2 100.4h.8l-.8 .2zM123.2 100.6l.8-.2v.2zM123.4 105.7v.1zM135.6 105.7v.1zM136.7 105.7l.2 1.1h-.3z"/>
<path d="M136.6 107.9h.3l-.2 1.1zM139.7 104.6l.1 1.1h-.3zM139.5 107.9h.3l-.1 1.1zM133.5 139.1l.4-.3-.2 .5zM134.4 139.1l.4-.3-.3 .5zM122.1 144.4h.1v.4zM122.2 144l.2 .1-.3 .3zM122.4 144.7l.2 .3-.4-.2zM122.2 144.4l.2 .3-.2 .1zM122.1 144.4l.3-.3-.2 .3zM122.4 144.7l.2 .1v.2zM122.2 144l.4-.2v.2z"/>
<path d="M122.2 144h.4l-.2 .1zM122.6 144.8h.3l-.3 .2zM122.6 144.8l.2-.1 .1 .1zM122.6 143.8l.2 .3-.2-.1zM122.9 144.4h.2l-.3 .3zM122.9 144v.4l-.1-.3zM122.6 143.8l.3 .2-.1 .1zM123.1 144.4l-.2 .4-.1-.1zM122.9 144l.2 .4h-.2zM133.5 145l.4-.3-.2 .4zM134.4 145l.4-.3-.3 .4zM143.9 144.4h.2v.4z"/>
<path d="M144.1 144l.1 .1-.3 .3zM144.2 144.7l.2 .3-.3-.2zM144.1 144.4l.1 .3-.1 .1zM144.2 144.1l-.1 .3h-.2zM144.2 144.7l.2 .1v.2zM144.1 144l.3-.2v.2zM144.1 144h.3l-.2 .1zM144.4 144.8h.4l-.4 .2zM144.4 144.8l.3-.1 .1 .1zM144.4 143.8l.3 .3-.3-.1zM144.8 144.4h.1l-.2 .3zM144.8 144v.4l-.1-.3z"/>
<path d="M144.4 143.8l.4 .2-.1 .1zM144.7 144.7l.2-.3-.1 .4zM144.8 144l.1 .4h-.1z"/>
<path d="M103 97.4v.3z" fill-rule="evenodd"/>
<path d="M103.2 96.9l.1 .1-.1 .5z" fill-rule="evenodd"/>
<path d="M103.2 100h.4h-.3v.2l.7 .1h-.7l-.1 .1z" fill-rule="evenodd"/>
<path d="M103.2 99.6l.9 .1h-.8v.3h.4h-.5z" fill-rule="evenodd"/>
<path d="M103.2 98l.2 .3z" fill-rule="evenodd"/>
<path d="M103.4 99.2h.4h-.4v.3z" fill-rule="evenodd"/>
<path d="M103.4 98.9l.1 .1-.1 .2z" fill-rule="evenodd"/>
<path d="M103.4 97.2l.1 .1a.87 .87 0 0 0-.3 .9l-.3 .4 .2-.5 .1-.6z" fill-rule="evenodd"/>
<path d="M103.6 97.3h.5h-.5v.2l.5 .1h-.5v.1z" fill-rule="evenodd"/>
<path d="M103.6 96.9l.6 .1-.6 .1v.2z" fill-rule="evenodd"/>
<path d="M103.3 100h.3v-.3h.4h-.3v.3z" fill-rule="evenodd"/>
<path d="M103.8 99h.1v.2z" fill-rule="evenodd"/>
<path d="M103.4 99.2h.5v.3l-.1-.3z" fill-rule="evenodd"/>
<path d="M103.8 98.1h.1l-.1 .5z" fill-rule="evenodd"/>
<path d="M103.2 100h.8v-.3h-.4h.5l-.1 .6-.3-.1h.3v-.2z" fill-rule="evenodd"/>
<path d="M103 99.2h1.1v-.1l.1 .1z" fill-rule="evenodd"/>
<path d="M103.4 97.8l.7-.1 .1 .2z" fill-rule="evenodd"/>
<path d="M103.6 97.3h.5v-.2l.1-.1-.1 .7v-.1l-.5-.1h.5v-.2z" fill-rule="evenodd"/>
<path d="M102.9 99.5h1.2l.1-.1 .1 .1z" fill-rule="evenodd"/>
<path d="M103.4 98.1h.7l.1-.1 .1 .1z" fill-rule="evenodd"/>
<path d="M104.7 99.5h.4h-.3v.4l.7 .1h-.7l.1 .5h-.2z" fill-rule="evenodd"/>
<path d="M104.7 96.9l.1 .1-.1 .2h-.1z" fill-rule="evenodd"/>
<path d="M104.7 97.9l.1 .5-.1 .1z" fill-rule="evenodd"/>
<path d="M104.5 97.9h.4v-.2l.1 .2z" fill-rule="evenodd"/>
<path d="M104.9 98.9l.2 .1-.1 .1 .3 .1h-.4l-.1 .3h.8h-.9l-.2 .2z" fill-rule="evenodd"/>
<path d="M104.6 97.2l.4-.1 .1 .2h-.4l-.1 .2h.4h-.4l-.1 .2z" fill-rule="evenodd"/>
<path d="M105.1 99.5h.4h-.3v.4h-.1z" fill-rule="evenodd"/>
<path d="M105.2 97.8h.5h-.5l-.2 .3z" fill-rule="evenodd"/>
<path d="M105.2 97.3h.4h-.4v.2h.4l-.4 .1z" fill-rule="evenodd"/>
<path d="M105.2 96.9l.6 .1h-.6v.3z" fill-rule="evenodd"/>
<path d="M105.3 97.5l.1 .1-.2 .1 .6 .1-.1 .6h-.1l.1-.6h-.5z" fill-rule="evenodd"/>
<path d="M105 99.1h.4l.1 .1-.3 .3h-.4h.4l.1-.3z" fill-rule="evenodd"/>
<path d="M105.4 98.4h.3l-.2 .2z" fill-rule="evenodd"/>
<path d="M105.3 97.8h.1v.2l-.4 .3z" fill-rule="evenodd"/>
<path d="M105.5 97.8h.1a.89 .89 0 0 1-.6 .8l.4-.5z" fill-rule="evenodd"/>
<path d="M104.7 99.5h.9v.6l-.8-.2h.7v-.4z" fill-rule="evenodd"/>
<path d="M105.2 97.2h.4v-.2h.2l-.1 .6-.5-.1h.4v-.2z" fill-rule="evenodd"/>
<path d="M106.3 97.6l.2 .6-.5 .4a.63 .63 0 0 0 .3-1z" fill-rule="evenodd"/>
<path d="M106.3 96.9l.2 .1-.2 .4h.5h-.5l-.2 .7z" fill-rule="evenodd"/>
<path d="M106.3 99l.2 .1-.4 .5h.3l-.3 .1-.1-.1z" fill-rule="evenodd"/>
<path d="M106.5 98.2l.9 .2a.67 .67 0 0 1-.9-.2z" fill-rule="evenodd"/>
<path d="M106.1 99.6h.3l.1-.3 .2 .1-.5 .7h.2l-.3 .1v-.1l.3-.5z" fill-rule="evenodd"/>
<path d="M106.6 97.4h.2l-.3 .7z" fill-rule="evenodd"/>
<path d="M106.9 99h.1l-.1 .2 .2 .1h-.2l-.2 .2 .6 .1h-.5v.4l.4 .1h-.4l.1 .5h-.2l-.1-1z" fill-rule="evenodd"/>
<path d="M106.9 96.9l.1 .1-.1 1.3z" fill-rule="evenodd"/>
<path d="M106.9 99.6h.3h-.2v.4z" fill-rule="evenodd"/>
<path d="M107 97.4l.3 .2v.2z" fill-rule="evenodd"/>
<path d="M106.9 99.2h.3l.1 .1-.3 .3 .1-.3z" fill-rule="evenodd"/>
<path d="M106.9 99.6h.4l-.1 .6v-.1l-.4-.1h.4v-.4z" fill-rule="evenodd"/>
<path d="M107.8 99l.2 .1-.4 .5h.3l-.3 .1-.1-.1z" fill-rule="evenodd"/>
<path d="M107.9 97.3l.7 .1h-.6v.2h.6h-.6l-.1 .1z" fill-rule="evenodd"/>
<path d="M107.6 99.6l.3-.1 .1-.2 .1 .1-.4 .6 .2 .1-.2 .1-.1-.1 .3-.5z" fill-rule="evenodd"/>
<path d="M107.7 100.1l.3-.1z" fill-rule="evenodd"/>
<path d="M108.1 96.9h.2v.2z" fill-rule="evenodd"/>
<path d="M108.3 99h.1v.2h.4h-.4l-.2 .2z" fill-rule="evenodd"/>
<path d="M108 100.2l.4-.3z" fill-rule="evenodd"/>
<path d="M108.4 99.7l.2 .3v.5l-.2 .2-.1-.2 .2-.1z" fill-rule="evenodd"/>
<path d="M108 98l.4-.1 .1 .1h-.4v.3h.3h-.3l-.1 .1z" fill-rule="evenodd"/>
<path d="M108 99.9l.5-.3z" fill-rule="evenodd"/>
<path d="M108.1 98.3h.3v-.3h.1v.4z" fill-rule="evenodd"/>
<path d="M108 97.6h.5v-.2h.1v.2z" fill-rule="evenodd"/>
<path d="M108.8 99.7l.1 .1-.2 .1a.33 .33 0 0 0 .3 .5l-.2 .1-.3-.6z" fill-rule="evenodd"/>
<path d="M108.2 99.4h.4v-.2h.2l-.2 .4v-.2z" fill-rule="evenodd"/>
<path d="M107.7 97.8h1l.1-.1 .1 .1h-1.1l-.1 .8z" fill-rule="evenodd"/>
<path d="M108.7 97.8h.2l-.1 .8h-.1l-.2-.1 .2-.1z" fill-rule="evenodd"/>
<path d="M107.6 97.1l1.3-.1 .1 .2z" fill-rule="evenodd"/>
<path d="M108 99.6h.8l.1-.1 .1 .1z" fill-rule="evenodd"/>
<path d="M109.2 99l.5 .1h-.4v.4h.2h-.2v.4l.2 .1h-.2l-.2 .7 .1-.6z" fill-rule="evenodd"/>
<path d="M109.3 97l1.2 .2h-1.1l-.1 .7-.2 .7 .2-.7z" fill-rule="evenodd"/>
<path d="M109.7 97.2l.1 .1-.1 .1z" fill-rule="evenodd"/>
<path d="M109.5 99.1h.2l-.1 1.4-.1 .1-.2-.1 .2-.1v-.4l-.2-.1h.2v-.4h-.2h.2z" fill-rule="evenodd"/>
<path d="M109.7 98a1.07 1.07 0 0 0 .8 .5l-.1 .1-.5-.2z" fill-rule="evenodd"/>
<path d="M109.7 97.5v.2h.5l-.5 .1z" fill-rule="evenodd"/>
<path d="M109.7 96.9l.2 .1v.1z" fill-rule="evenodd"/>
<path d="M109.3 98.6l.5-.3 .1 .1z" fill-rule="evenodd"/>
<path d="M109.8 99.8l.2 .5z" fill-rule="evenodd"/>
<path d="M109.9 99.4l.1 .1-.3 .3z" fill-rule="evenodd"/>
<path d="M109.9 98.9l.2 .2v.1z" fill-rule="evenodd"/>
<path d="M109.7 97.4h.4v-.2l.1 .1v.1z" fill-rule="evenodd"/>
<path d="M109.7 97.7h.4v-.2h.1v.2z" fill-rule="evenodd"/>
<path d="M110.2 99.4l.2 .3v.1z" fill-rule="evenodd"/>
<path d="M109.5 97.9h.7l.1 .1z" fill-rule="evenodd"/>
<path d="M110.2 99.7l.1 .1-.2 .5 .4 .2-.1 .2-.5-.4z" fill-rule="evenodd"/>
<path d="M110.1 98h.2l-.3 .3-.1-.1z" fill-rule="evenodd"/>
<path d="M109.4 97.4h.9l.2 .1z" fill-rule="evenodd"/>
<path d="M109.7 99.3l.7-.1 .1 .1z" fill-rule="evenodd"/>
<path d="M110.9 99l.2 .1-.3 .5h.2l-.2 .2-.2-.2z" fill-rule="evenodd"/>
<path d="M110.8 97.2h.3a.75 .75 0 0 0-.1 1.2 .73 .73 0 0 1-.3-1z" fill-rule="evenodd"/>
<path d="M111 97.2l.2 .1 .1 .6a.51 .51 0 0 1-.3 .5h-.2a.75 .75 0 0 0 .2-1.2z" fill-rule="evenodd"/>
<path d="M110.8 99.6h.2l.1-.3 .1 .1-.4 .7h.2l-.2 .1-.1-.1 .3-.5z" fill-rule="evenodd"/>
<path d="M111.3 99.1l.1 .1-.1 .5h.7h-.7v.8h-.1z" fill-rule="evenodd"/>
<path d="M111.5 98.2h.1l-.1 .2z" fill-rule="evenodd"/>
<path d="M111.6 99.2l.1 .5h-.1z" fill-rule="evenodd"/>
<path d="M111.6 99.7h.1v.5l.3 .4a.87 .87 0 0 1-.4-.9z" fill-rule="evenodd"/>
<path d="M111.3 99.2l.6-.2v.1z" fill-rule="evenodd"/>
<path d="M112.6 97.1l-.4 .9h.6h-.1v.3l.1 .1h-.4l.2-.1v-.3h-.4z" fill-rule="evenodd"/>
<path d="M112.7 97.1v.9h-.5h.4z" fill-rule="evenodd"/>
<path d="M113 98.1h.1v.2l.2 .1h-.2z" fill-rule="evenodd"/>
<path d="M113.2 97.6h.3l-.5 .2z" fill-rule="evenodd"/>
<path d="M113.3 99.2l.1-.1a.98 .98 0 0 0 0 1.5 .91 .91 0 0 1-.1-1.4z" fill-rule="evenodd"/>
<path d="M113.3 97.7l.2-.1 .1 .4a.33 .33 0 0 1-.1 .3 .33 .33 0 0 1-.4 .1 .37 .37 0 0 0 .4-.3 .37 .37 0 0 0-.2-.4z" fill-rule="evenodd"/>
<path d="M113 97.1h.5v.1h-.4l-.1 .6z" fill-rule="evenodd"/>
<path d="M113.7 97.2l.2 1.2h-.2z" fill-rule="evenodd"/>
<path d="M113.7 97.1h.2l.1 1.3z" fill-rule="evenodd"/>
<path d="M113.9 99.2h.3l-.1 .1v1.1l.1 .1h-.3l.1-.1z" fill-rule="evenodd"/>
<path d="M114.3 97.2v1.1l.1 .1h-.3l.1-.1z" fill-rule="evenodd"/>
<path d="M113.8 99.2h.5l-.5 .1-.1 .2z" fill-rule="evenodd"/>
<path d="M113.9 99.2h.4l.1 .3-.2-.3z" fill-rule="evenodd"/>
<path d="M114.2 97.1l.2 .1-.2 .1-.2 1.1z" fill-rule="evenodd"/>
<path d="M114.8 97.1l-.2 .8h.3h-.3v.4l.1 .1h-.2z" fill-rule="evenodd"/>
<path d="M114.8 97.1h.1l.3 1.3h-.3l.1-.1-.1-.4h-.3h.3z" fill-rule="evenodd"/>
<path d="M115.3 97.1h.2v.2l.4 1.1h-.2v-.1z" fill-rule="evenodd"/>
<path d="M115.6 97.8l-.2 .5 .1 .1h-.3z" fill-rule="evenodd"/>
<path d="M115.5 99.2h.2a.78 .78 0 0 0-.3 1.1l.2 .1-.1 .1a1.01 1.01 0 0 1 0-1.3z" fill-rule="evenodd"/>
<path d="M115.6 99.2h.1a.93 .93 0 0 1-.1 1.3h-.1a.79 .79 0 0 0 .2-1.1z" fill-rule="evenodd"/>
<path d="M115.7 97.1l.2 .1-.3 .5 .1-.4z" fill-rule="evenodd"/>
<path d="M117 99.2h.2l-.2 .1a.89 .89 0 0 0 0 .9l.1 .2-.1 .1a1.24 1.24 0 0 1 0-1.3z" fill-rule="evenodd"/>
<path d="M117.1 99.2h.1a.93 .93 0 0 1-.1 1.3h-.1a.64 .64 0 0 0 .3-.9z" fill-rule="evenodd"/>
<path d="M117.7 99.8l.2-.1h.2l-.3 .1-.1 .1z" fill-rule="evenodd"/>
<path d="M117.9 99.7h.2a.59 .59 0 0 1-.1 .8h-.2l.2-.1 .1-.2v-.3z" fill-rule="evenodd"/>
<path d="M117.7 99.2h.5v.1h-.5v.6z" fill-rule="evenodd"/>
<path d="M118.3 99.7l.2-.1v.9h-.2z" fill-rule="evenodd"/>
<path d="M118.5 99.7h.2l-.2 .1z" fill-rule="evenodd"/>
<path d="M118.6 99.7h.1l-.1 .1z" fill-rule="evenodd"/>
<path d="M118.8 99.7h.2h-.2v.8h-.2v-.7z" fill-rule="evenodd"/>
<path d="M118.9 99.7h.1v.8h-.1z" fill-rule="evenodd"/>
<path d="M119.1 99.7l.1-.1 .1 .9h-.2z" fill-rule="evenodd"/>
<path d="M119.3 99.7h.2l-.3 .1z" fill-rule="evenodd"/>
<path d="M119.4 99.7h.1l-.1 .1z" fill-rule="evenodd"/>
<path d="M119.6 99.7h.1l-.2 .1 .1 .7h-.2v-.7z" fill-rule="evenodd"/>
<path d="M119.6 99.7l.2 .1v.7h-.2z" fill-rule="evenodd"/>
<path d="M120 99.1a.87 .87 0 0 1 0 1.5 .96 .96 0 0 0 0-1.5z" fill-rule="evenodd"/>
<path d="M235.5 96.1h.2l-.1 .1v1.1l.1 .1h-.2z" fill-rule="evenodd"/>
<path d="M235.5 82.4h.3l-.1 .1v1.1h.1h-.3z" fill-rule="evenodd"/>
<path d="M235.5 93.4h.3h-.1v1.1l.1 .1h-.3z" fill-rule="evenodd"/>
<path d="M235.4 85.1h.2v1.3z" fill-rule="evenodd"/>
<path d="M235.5 96.1a.66 .66 0 0 1 .7 .6 .66 .66 0 0 1-.7 .7h.3a.65 .65 0 0 0 .3-.8 .65 .65 0 0 0-.6-.5z" fill-rule="evenodd"/>
<path d="M235.8 85.4l-.2 1z" fill-rule="evenodd"/>
<path d="M235.5 82.4a.67 .67 0 0 1 .8 .5 .67 .67 0 0 1-.5 .8h-.3v-.1h.3a.64 .64 0 0 0 .4-.7 .64 .64 0 0 0-.7-.5z" fill-rule="evenodd"/>
<path d="M235.5 93.3l.5 .1a.74 .74 0 0 1-.2 1.2h-.3h.3a.74 .74 0 0 0 0-1.2z" fill-rule="evenodd"/>
<path d="M235.7 85.1h.3v1.3z" fill-rule="evenodd"/>
<path d="M236.1 85.1h.1l-.2 1.3z" fill-rule="evenodd"/>
<path d="M236.3 96.1h.4l-.2 .1v.4l.3 .1h-.3l.1 .7h-.3z" fill-rule="evenodd"/>
<path d="M236.4 85.1h.3l-.2 .1v.5h.3h-.3l.1 .7h-.3l.1-.1z" fill-rule="evenodd"/>
<path d="M236.4 93.4h.3h-.1v.5h.3l-.3 .1 .1 .6h-.3l.1-1.2z" fill-rule="evenodd"/>
<path d="M236.3 96.1h.6l.1 .2v.2l-.2 .2-.3-.1h.3v-.4z" fill-rule="evenodd"/>
<path d="M236.3 85.1l.7 .1v.4l-.2 .1h-.3h.2a.32 .32 0 0 0 .1-.5z" fill-rule="evenodd"/>
<path d="M236.7 85.7h.1l.3 .7h-.2z" fill-rule="evenodd"/>
<path d="M236.4 93.3l.5 .1 .2 .1-.2 .4h-.3h.2a.29 .29 0 0 0 .1-.5z" fill-rule="evenodd"/>
<path d="M236.7 96.7a.33 .33 0 0 1 .4 .3 .33 .33 0 0 1-.4 .4h-.4h.4a.32 .32 0 0 0 .3-.4 .32 .32 0 0 0-.3-.3z" fill-rule="evenodd"/>
<path d="M236.6 82.4h.4a.41 .41 0 0 0-.5 .5 .51 .51 0 0 0 .3 .7h-.1a.88 .88 0 0 1-.1-1.2z" fill-rule="evenodd"/>
<path d="M236.7 94a.35 .35 0 0 1 .5 .3 .35 .35 0 0 1-.4 .3h-.4l.6-.1v-.4z" fill-rule="evenodd"/>
<path d="M236.7 83.6h.3l.2-.3-.2 .3z" fill-rule="evenodd"/>
<path d="M236.8 82.4l.3-.1 .1 .4z" fill-rule="evenodd"/>
<path d="M237.4 93.5l.2-.2 .2 .1a.73 .73 0 0 0-.2 1.2 .78 .78 0 0 1-.2-1.1z" fill-rule="evenodd"/>
<path d="M237.3 96.2l.3-.1v1.1l.2 .2h-.5l.2-.2v-.9z" fill-rule="evenodd"/>
<path d="M237.6 93.4h.2a.99 .99 0 0 1 0 1.2h-.3a.74 .74 0 0 0 .3-1.1z" fill-rule="evenodd"/>
<path d="M103 100.7l.4-.4 .1 .1z" fill-rule="evenodd"/>
<path d="M103.3 100.2h.3v-.2h.4h-.3v.2z" fill-rule="evenodd"/>
<path d="M103.7 100.3l.4 .1 .1 .2z" fill-rule="evenodd"/>
<path d="M104.7 100.5h.9l.2-.4 .1 .4-.2 .1z" fill-rule="evenodd"/>
<path d="M106 100.5l.6-.2-.5 .3z" fill-rule="evenodd"/>
<path d="M106.7 100.6h.5l.1-.4 .1 .3-.1 .1z" fill-rule="evenodd"/>
<path d="M107.6 100.4l.5-.1-.5 .2z" fill-rule="evenodd"/>
<path d="M108 100.6l.5-.5v.1z" fill-rule="evenodd"/>
<path d="M109.5 100.7l.4-.4 .1 .1z" fill-rule="evenodd"/>
<path d="M110.6 100.4l.6-.1-.5 .3z" fill-rule="evenodd"/>
<path d="M111.2 100.5l.4-.2-.3 .4z" fill-rule="evenodd"/>
<path d="M116.1 100.3h.1v.2h-.1z" fill-rule="evenodd"/>
<path d="M117.6 100.2l.3 .3-.2-.1z" fill-rule="evenodd"/>
</g>
<path d="M103.6 99.5h.1v.2h-.1zM103.8 97.9h.1v.2h-.1zM104.7 97.5l.1 .4zM114.5 100h.7v.1h-.7zM114.5 99.6l.7 .1z" fill="#000"/>
<path d="M96.5 90.5v18.5M96.6 104.6v4.4" fill="none" stroke="#000" stroke-width=".19"/>
<use href="#words"/>
</svg>
